VERSION 5.8 ;
BUSBITCHARS "[]" ;
DIVIDERCHAR "/" ;
UNITS
    DATABASE MICRONS 1000 ;
END UNITS

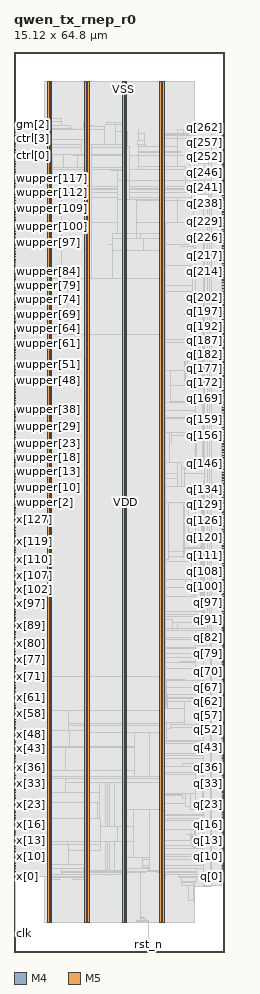
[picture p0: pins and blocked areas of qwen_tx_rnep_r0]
MACRO qwen_tx_rnep_r0
  FOREIGN qwen_tx_rnep_r0 0 0 ;
  CLASS BLOCK ;
  SIZE 15.12 BY 64.8 ;
  PIN clk
    DIRECTION INPUT ;
    USE SIGNAL ;
    PORT
      LAYER M4 ;
        RECT  0.054 1.296 0.138 1.32 ;
    END
    PORT
      LAYER M4 ;
        RECT  0.108 1.296 0.227 1.416 ;
    END
  END clk
  PIN ctrl[0]
    DIRECTION INPUT ;
    USE SIGNAL ;
    PORT
      LAYER M4 ;
        RECT  0.054 57.36 0.138 57.384 ;
    END
  END ctrl[0]
  PIN ctrl[1]
    DIRECTION INPUT ;
    USE SIGNAL ;
    PORT
      LAYER M4 ;
        RECT  0.054 57.552 0.138 57.576 ;
    END
  END ctrl[1]
  PIN ctrl[2]
    DIRECTION INPUT ;
    USE SIGNAL ;
    PORT
      LAYER M4 ;
        RECT  0.054 57.744 0.138 57.768 ;
    END
  END ctrl[2]
  PIN ctrl[3]
    DIRECTION INPUT ;
    USE SIGNAL ;
    PORT
      LAYER M4 ;
        RECT  0.054 57.984 0.138 58.008 ;
    END
  END ctrl[3]
  PIN ctrl[4]
    DIRECTION INPUT ;
    USE SIGNAL ;
    PORT
      LAYER M4 ;
        RECT  0.054 58.176 0.138 58.2 ;
    END
  END ctrl[4]
  PIN ctrl[5]
    DIRECTION INPUT ;
    USE SIGNAL ;
    PORT
      LAYER M4 ;
        RECT  0.054 58.368 0.138 58.392 ;
    END
  END ctrl[5]
  PIN gm[0]
    DIRECTION INPUT ;
    USE SIGNAL ;
    PORT
      LAYER M4 ;
        RECT  0.054 58.56 0.138 58.584 ;
    END
  END gm[0]
  PIN gm[1]
    DIRECTION INPUT ;
    USE SIGNAL ;
    PORT
      LAYER M4 ;
        RECT  0.054 58.8 0.138 58.824 ;
    END
  END gm[1]
  PIN gm[2]
    DIRECTION INPUT ;
    USE SIGNAL ;
    PORT
      LAYER M4 ;
        RECT  0.054 58.992 0.138 59.016 ;
    END
  END gm[2]
  PIN gm[3]
    DIRECTION INPUT ;
    USE SIGNAL ;
    PORT
      LAYER M4 ;
        RECT  0.054 59.184 0.138 59.208 ;
    END
  END gm[3]
  PIN q[0]
    DIRECTION OUTPUT ;
    USE SIGNAL ;
    PORT
      LAYER M4 ;
        RECT  14.982 5.424 15.066 5.448 ;
    END
  END q[0]
  PIN q[100]
    DIRECTION OUTPUT ;
    USE SIGNAL ;
    PORT
      LAYER M4 ;
        RECT  14.982 25.776 15.066 25.8 ;
    END
  END q[100]
  PIN q[101]
    DIRECTION OUTPUT ;
    USE SIGNAL ;
    PORT
      LAYER M4 ;
        RECT  14.982 25.968 15.066 25.992 ;
    END
  END q[101]
  PIN q[102]
    DIRECTION OUTPUT ;
    USE SIGNAL ;
    PORT
      LAYER M4 ;
        RECT  14.982 26.16 15.066 26.184 ;
    END
  END q[102]
  PIN q[103]
    DIRECTION OUTPUT ;
    USE SIGNAL ;
    PORT
      LAYER M4 ;
        RECT  14.982 26.4 15.066 26.424 ;
    END
  END q[103]
  PIN q[104]
    DIRECTION OUTPUT ;
    USE SIGNAL ;
    PORT
      LAYER M4 ;
        RECT  14.982 26.592 15.066 26.616 ;
    END
  END q[104]
  PIN q[105]
    DIRECTION OUTPUT ;
    USE SIGNAL ;
    PORT
      LAYER M4 ;
        RECT  14.982 26.784 15.066 26.808 ;
    END
  END q[105]
  PIN q[106]
    DIRECTION OUTPUT ;
    USE SIGNAL ;
    PORT
      LAYER M4 ;
        RECT  14.982 26.976 15.066 27 ;
    END
  END q[106]
  PIN q[107]
    DIRECTION OUTPUT ;
    USE SIGNAL ;
    PORT
      LAYER M4 ;
        RECT  14.982 27.168 15.066 27.192 ;
    END
  END q[107]
  PIN q[108]
    DIRECTION OUTPUT ;
    USE SIGNAL ;
    PORT
      LAYER M4 ;
        RECT  14.982 27.408 15.066 27.432 ;
    END
  END q[108]
  PIN q[109]
    DIRECTION OUTPUT ;
    USE SIGNAL ;
    PORT
      LAYER M4 ;
        RECT  14.982 27.6 15.066 27.624 ;
    END
  END q[109]
  PIN q[10]
    DIRECTION OUTPUT ;
    USE SIGNAL ;
    PORT
      LAYER M4 ;
        RECT  14.982 7.44 15.066 7.464 ;
    END
  END q[10]
  PIN q[110]
    DIRECTION OUTPUT ;
    USE SIGNAL ;
    PORT
      LAYER M4 ;
        RECT  14.982 27.792 15.066 27.816 ;
    END
  END q[110]
  PIN q[111]
    DIRECTION OUTPUT ;
    USE SIGNAL ;
    PORT
      LAYER M4 ;
        RECT  14.982 27.984 15.066 28.008 ;
    END
  END q[111]
  PIN q[112]
    DIRECTION OUTPUT ;
    USE SIGNAL ;
    PORT
      LAYER M4 ;
        RECT  14.982 28.224 15.066 28.248 ;
    END
  END q[112]
  PIN q[113]
    DIRECTION OUTPUT ;
    USE SIGNAL ;
    PORT
      LAYER M4 ;
        RECT  14.982 28.416 15.066 28.44 ;
    END
  END q[113]
  PIN q[114]
    DIRECTION OUTPUT ;
    USE SIGNAL ;
    PORT
      LAYER M4 ;
        RECT  14.982 28.608 15.066 28.632 ;
    END
  END q[114]
  PIN q[115]
    DIRECTION OUTPUT ;
    USE SIGNAL ;
    PORT
      LAYER M4 ;
        RECT  14.982 28.8 15.066 28.824 ;
    END
  END q[115]
  PIN q[116]
    DIRECTION OUTPUT ;
    USE SIGNAL ;
    PORT
      LAYER M4 ;
        RECT  14.982 29.04 15.066 29.064 ;
    END
  END q[116]
  PIN q[117]
    DIRECTION OUTPUT ;
    USE SIGNAL ;
    PORT
      LAYER M4 ;
        RECT  14.982 29.232 15.066 29.256 ;
    END
  END q[117]
  PIN q[118]
    DIRECTION OUTPUT ;
    USE SIGNAL ;
    PORT
      LAYER M4 ;
        RECT  14.982 29.424 15.066 29.448 ;
    END
  END q[118]
  PIN q[119]
    DIRECTION OUTPUT ;
    USE SIGNAL ;
    PORT
      LAYER M4 ;
        RECT  14.982 29.616 15.066 29.64 ;
    END
  END q[119]
  PIN q[11]
    DIRECTION OUTPUT ;
    USE SIGNAL ;
    PORT
      LAYER M4 ;
        RECT  14.982 7.632 15.066 7.656 ;
    END
  END q[11]
  PIN q[120]
    DIRECTION OUTPUT ;
    USE SIGNAL ;
    PORT
      LAYER M4 ;
        RECT  14.982 29.856 15.066 29.88 ;
    END
  END q[120]
  PIN q[121]
    DIRECTION OUTPUT ;
    USE SIGNAL ;
    PORT
      LAYER M4 ;
        RECT  14.982 30.048 15.066 30.072 ;
    END
  END q[121]
  PIN q[122]
    DIRECTION OUTPUT ;
    USE SIGNAL ;
    PORT
      LAYER M4 ;
        RECT  14.982 30.24 15.066 30.264 ;
    END
  END q[122]
  PIN q[123]
    DIRECTION OUTPUT ;
    USE SIGNAL ;
    PORT
      LAYER M4 ;
        RECT  14.982 30.432 15.066 30.456 ;
    END
  END q[123]
  PIN q[124]
    DIRECTION OUTPUT ;
    USE SIGNAL ;
    PORT
      LAYER M4 ;
        RECT  14.982 30.672 15.066 30.696 ;
    END
  END q[124]
  PIN q[125]
    DIRECTION OUTPUT ;
    USE SIGNAL ;
    PORT
      LAYER M4 ;
        RECT  14.982 30.864 15.066 30.888 ;
    END
  END q[125]
  PIN q[126]
    DIRECTION OUTPUT ;
    USE SIGNAL ;
    PORT
      LAYER M4 ;
        RECT  14.982 31.056 15.066 31.08 ;
    END
  END q[126]
  PIN q[127]
    DIRECTION OUTPUT ;
    USE SIGNAL ;
    PORT
      LAYER M4 ;
        RECT  14.982 31.248 15.066 31.272 ;
    END
  END q[127]
  PIN q[128]
    DIRECTION OUTPUT ;
    USE SIGNAL ;
    PORT
      LAYER M4 ;
        RECT  14.982 31.488 15.066 31.512 ;
    END
  END q[128]
  PIN q[129]
    DIRECTION OUTPUT ;
    USE SIGNAL ;
    PORT
      LAYER M4 ;
        RECT  14.982 31.68 15.066 31.704 ;
    END
  END q[129]
  PIN q[12]
    DIRECTION OUTPUT ;
    USE SIGNAL ;
    PORT
      LAYER M4 ;
        RECT  14.982 7.824 15.066 7.848 ;
    END
  END q[12]
  PIN q[130]
    DIRECTION OUTPUT ;
    USE SIGNAL ;
    PORT
      LAYER M4 ;
        RECT  14.982 31.872 15.066 31.896 ;
    END
  END q[130]
  PIN q[131]
    DIRECTION OUTPUT ;
    USE SIGNAL ;
    PORT
      LAYER M4 ;
        RECT  14.982 32.064 15.066 32.088 ;
    END
  END q[131]
  PIN q[132]
    DIRECTION OUTPUT ;
    USE SIGNAL ;
    PORT
      LAYER M4 ;
        RECT  14.982 32.304 15.066 32.328 ;
    END
  END q[132]
  PIN q[133]
    DIRECTION OUTPUT ;
    USE SIGNAL ;
    PORT
      LAYER M4 ;
        RECT  14.982 32.496 15.066 32.52 ;
    END
  END q[133]
  PIN q[134]
    DIRECTION OUTPUT ;
    USE SIGNAL ;
    PORT
      LAYER M4 ;
        RECT  14.982 32.688 15.066 32.712 ;
    END
  END q[134]
  PIN q[135]
    DIRECTION OUTPUT ;
    USE SIGNAL ;
    PORT
      LAYER M4 ;
        RECT  14.982 32.88 15.066 32.904 ;
    END
  END q[135]
  PIN q[136]
    DIRECTION OUTPUT ;
    USE SIGNAL ;
    PORT
      LAYER M4 ;
        RECT  14.982 33.12 15.066 33.144 ;
    END
  END q[136]
  PIN q[137]
    DIRECTION OUTPUT ;
    USE SIGNAL ;
    PORT
      LAYER M4 ;
        RECT  14.982 33.312 15.066 33.336 ;
    END
  END q[137]
  PIN q[138]
    DIRECTION OUTPUT ;
    USE SIGNAL ;
    PORT
      LAYER M4 ;
        RECT  14.982 33.504 15.066 33.528 ;
    END
  END q[138]
  PIN q[139]
    DIRECTION OUTPUT ;
    USE SIGNAL ;
    PORT
      LAYER M4 ;
        RECT  14.982 33.696 15.066 33.72 ;
    END
  END q[139]
  PIN q[13]
    DIRECTION OUTPUT ;
    USE SIGNAL ;
    PORT
      LAYER M4 ;
        RECT  14.982 8.016 15.066 8.04 ;
    END
  END q[13]
  PIN q[140]
    DIRECTION OUTPUT ;
    USE SIGNAL ;
    PORT
      LAYER M4 ;
        RECT  14.982 33.936 15.066 33.96 ;
    END
  END q[140]
  PIN q[141]
    DIRECTION OUTPUT ;
    USE SIGNAL ;
    PORT
      LAYER M4 ;
        RECT  14.982 34.128 15.066 34.152 ;
    END
  END q[141]
  PIN q[142]
    DIRECTION OUTPUT ;
    USE SIGNAL ;
    PORT
      LAYER M4 ;
        RECT  14.982 34.32 15.066 34.344 ;
    END
  END q[142]
  PIN q[143]
    DIRECTION OUTPUT ;
    USE SIGNAL ;
    PORT
      LAYER M4 ;
        RECT  14.982 34.512 15.066 34.536 ;
    END
  END q[143]
  PIN q[144]
    DIRECTION OUTPUT ;
    USE SIGNAL ;
    PORT
      LAYER M4 ;
        RECT  14.982 34.752 15.066 34.776 ;
    END
  END q[144]
  PIN q[145]
    DIRECTION OUTPUT ;
    USE SIGNAL ;
    PORT
      LAYER M4 ;
        RECT  14.982 34.944 15.066 34.968 ;
    END
  END q[145]
  PIN q[146]
    DIRECTION OUTPUT ;
    USE SIGNAL ;
    PORT
      LAYER M4 ;
        RECT  14.982 35.136 15.066 35.16 ;
    END
  END q[146]
  PIN q[147]
    DIRECTION OUTPUT ;
    USE SIGNAL ;
    PORT
      LAYER M4 ;
        RECT  14.982 35.328 15.066 35.352 ;
    END
  END q[147]
  PIN q[148]
    DIRECTION OUTPUT ;
    USE SIGNAL ;
    PORT
      LAYER M4 ;
        RECT  14.982 35.568 15.066 35.592 ;
    END
  END q[148]
  PIN q[149]
    DIRECTION OUTPUT ;
    USE SIGNAL ;
    PORT
      LAYER M4 ;
        RECT  14.982 35.76 15.066 35.784 ;
    END
  END q[149]
  PIN q[14]
    DIRECTION OUTPUT ;
    USE SIGNAL ;
    PORT
      LAYER M4 ;
        RECT  14.982 8.256 15.066 8.28 ;
    END
  END q[14]
  PIN q[150]
    DIRECTION OUTPUT ;
    USE SIGNAL ;
    PORT
      LAYER M4 ;
        RECT  14.982 35.952 15.066 35.976 ;
    END
  END q[150]
  PIN q[151]
    DIRECTION OUTPUT ;
    USE SIGNAL ;
    PORT
      LAYER M4 ;
        RECT  14.982 36.144 15.066 36.168 ;
    END
  END q[151]
  PIN q[152]
    DIRECTION OUTPUT ;
    USE SIGNAL ;
    PORT
      LAYER M4 ;
        RECT  14.982 36.384 15.066 36.408 ;
    END
  END q[152]
  PIN q[153]
    DIRECTION OUTPUT ;
    USE SIGNAL ;
    PORT
      LAYER M4 ;
        RECT  14.982 36.576 15.066 36.6 ;
    END
  END q[153]
  PIN q[154]
    DIRECTION OUTPUT ;
    USE SIGNAL ;
    PORT
      LAYER M4 ;
        RECT  14.982 36.768 15.066 36.792 ;
    END
  END q[154]
  PIN q[155]
    DIRECTION OUTPUT ;
    USE SIGNAL ;
    PORT
      LAYER M4 ;
        RECT  14.982 36.96 15.066 36.984 ;
    END
  END q[155]
  PIN q[156]
    DIRECTION OUTPUT ;
    USE SIGNAL ;
    PORT
      LAYER M4 ;
        RECT  14.982 37.2 15.066 37.224 ;
    END
  END q[156]
  PIN q[157]
    DIRECTION OUTPUT ;
    USE SIGNAL ;
    PORT
      LAYER M4 ;
        RECT  14.982 37.392 15.066 37.416 ;
    END
  END q[157]
  PIN q[158]
    DIRECTION OUTPUT ;
    USE SIGNAL ;
    PORT
      LAYER M4 ;
        RECT  14.982 37.584 15.066 37.608 ;
    END
  END q[158]
  PIN q[159]
    DIRECTION OUTPUT ;
    USE SIGNAL ;
    PORT
      LAYER M4 ;
        RECT  14.982 37.776 15.066 37.8 ;
    END
  END q[159]
  PIN q[15]
    DIRECTION OUTPUT ;
    USE SIGNAL ;
    PORT
      LAYER M4 ;
        RECT  14.982 8.448 15.066 8.472 ;
    END
  END q[15]
  PIN q[160]
    DIRECTION OUTPUT ;
    USE SIGNAL ;
    PORT
      LAYER M4 ;
        RECT  14.982 37.968 15.066 37.992 ;
    END
  END q[160]
  PIN q[161]
    DIRECTION OUTPUT ;
    USE SIGNAL ;
    PORT
      LAYER M4 ;
        RECT  14.982 38.208 15.066 38.232 ;
    END
  END q[161]
  PIN q[162]
    DIRECTION OUTPUT ;
    USE SIGNAL ;
    PORT
      LAYER M4 ;
        RECT  14.982 38.4 15.066 38.424 ;
    END
  END q[162]
  PIN q[163]
    DIRECTION OUTPUT ;
    USE SIGNAL ;
    PORT
      LAYER M4 ;
        RECT  14.982 38.592 15.066 38.616 ;
    END
  END q[163]
  PIN q[164]
    DIRECTION OUTPUT ;
    USE SIGNAL ;
    PORT
      LAYER M4 ;
        RECT  14.982 38.784 15.066 38.808 ;
    END
  END q[164]
  PIN q[165]
    DIRECTION OUTPUT ;
    USE SIGNAL ;
    PORT
      LAYER M4 ;
        RECT  14.982 39.024 15.066 39.048 ;
    END
  END q[165]
  PIN q[166]
    DIRECTION OUTPUT ;
    USE SIGNAL ;
    PORT
      LAYER M4 ;
        RECT  14.982 39.216 15.066 39.24 ;
    END
  END q[166]
  PIN q[167]
    DIRECTION OUTPUT ;
    USE SIGNAL ;
    PORT
      LAYER M4 ;
        RECT  14.982 39.408 15.066 39.432 ;
    END
  END q[167]
  PIN q[168]
    DIRECTION OUTPUT ;
    USE SIGNAL ;
    PORT
      LAYER M4 ;
        RECT  14.982 39.6 15.066 39.624 ;
    END
  END q[168]
  PIN q[169]
    DIRECTION OUTPUT ;
    USE SIGNAL ;
    PORT
      LAYER M4 ;
        RECT  14.982 39.84 15.066 39.864 ;
    END
  END q[169]
  PIN q[16]
    DIRECTION OUTPUT ;
    USE SIGNAL ;
    PORT
      LAYER M4 ;
        RECT  14.982 8.64 15.066 8.664 ;
    END
  END q[16]
  PIN q[170]
    DIRECTION OUTPUT ;
    USE SIGNAL ;
    PORT
      LAYER M4 ;
        RECT  14.982 40.032 15.066 40.056 ;
    END
  END q[170]
  PIN q[171]
    DIRECTION OUTPUT ;
    USE SIGNAL ;
    PORT
      LAYER M4 ;
        RECT  14.982 40.224 15.066 40.248 ;
    END
  END q[171]
  PIN q[172]
    DIRECTION OUTPUT ;
    USE SIGNAL ;
    PORT
      LAYER M4 ;
        RECT  14.982 40.416 15.066 40.44 ;
    END
  END q[172]
  PIN q[173]
    DIRECTION OUTPUT ;
    USE SIGNAL ;
    PORT
      LAYER M4 ;
        RECT  14.982 40.656 15.066 40.68 ;
    END
  END q[173]
  PIN q[174]
    DIRECTION OUTPUT ;
    USE SIGNAL ;
    PORT
      LAYER M4 ;
        RECT  14.982 40.848 15.066 40.872 ;
    END
  END q[174]
  PIN q[175]
    DIRECTION OUTPUT ;
    USE SIGNAL ;
    PORT
      LAYER M4 ;
        RECT  14.982 41.04 15.066 41.064 ;
    END
  END q[175]
  PIN q[176]
    DIRECTION OUTPUT ;
    USE SIGNAL ;
    PORT
      LAYER M4 ;
        RECT  14.982 41.232 15.066 41.256 ;
    END
  END q[176]
  PIN q[177]
    DIRECTION OUTPUT ;
    USE SIGNAL ;
    PORT
      LAYER M4 ;
        RECT  14.982 41.472 15.066 41.496 ;
    END
  END q[177]
  PIN q[178]
    DIRECTION OUTPUT ;
    USE SIGNAL ;
    PORT
      LAYER M4 ;
        RECT  14.982 41.664 15.066 41.688 ;
    END
  END q[178]
  PIN q[179]
    DIRECTION OUTPUT ;
    USE SIGNAL ;
    PORT
      LAYER M4 ;
        RECT  14.982 41.856 15.066 41.88 ;
    END
  END q[179]
  PIN q[17]
    DIRECTION OUTPUT ;
    USE SIGNAL ;
    PORT
      LAYER M4 ;
        RECT  14.982 8.832 15.066 8.856 ;
    END
  END q[17]
  PIN q[180]
    DIRECTION OUTPUT ;
    USE SIGNAL ;
    PORT
      LAYER M4 ;
        RECT  14.982 42.048 15.066 42.072 ;
    END
  END q[180]
  PIN q[181]
    DIRECTION OUTPUT ;
    USE SIGNAL ;
    PORT
      LAYER M4 ;
        RECT  14.982 42.288 15.066 42.312 ;
    END
  END q[181]
  PIN q[182]
    DIRECTION OUTPUT ;
    USE SIGNAL ;
    PORT
      LAYER M4 ;
        RECT  14.982 42.48 15.066 42.504 ;
    END
  END q[182]
  PIN q[183]
    DIRECTION OUTPUT ;
    USE SIGNAL ;
    PORT
      LAYER M4 ;
        RECT  14.982 42.672 15.066 42.696 ;
    END
  END q[183]
  PIN q[184]
    DIRECTION OUTPUT ;
    USE SIGNAL ;
    PORT
      LAYER M4 ;
        RECT  14.982 42.864 15.066 42.888 ;
    END
  END q[184]
  PIN q[185]
    DIRECTION OUTPUT ;
    USE SIGNAL ;
    PORT
      LAYER M4 ;
        RECT  14.982 43.104 15.066 43.128 ;
    END
  END q[185]
  PIN q[186]
    DIRECTION OUTPUT ;
    USE SIGNAL ;
    PORT
      LAYER M4 ;
        RECT  14.982 43.296 15.066 43.32 ;
    END
  END q[186]
  PIN q[187]
    DIRECTION OUTPUT ;
    USE SIGNAL ;
    PORT
      LAYER M4 ;
        RECT  14.982 43.488 15.066 43.512 ;
    END
  END q[187]
  PIN q[188]
    DIRECTION OUTPUT ;
    USE SIGNAL ;
    PORT
      LAYER M4 ;
        RECT  14.982 43.68 15.066 43.704 ;
    END
  END q[188]
  PIN q[189]
    DIRECTION OUTPUT ;
    USE SIGNAL ;
    PORT
      LAYER M4 ;
        RECT  14.982 43.92 15.066 43.944 ;
    END
  END q[189]
  PIN q[18]
    DIRECTION OUTPUT ;
    USE SIGNAL ;
    PORT
      LAYER M4 ;
        RECT  14.982 9.072 15.066 9.096 ;
    END
  END q[18]
  PIN q[190]
    DIRECTION OUTPUT ;
    USE SIGNAL ;
    PORT
      LAYER M4 ;
        RECT  14.982 44.112 15.066 44.136 ;
    END
  END q[190]
  PIN q[191]
    DIRECTION OUTPUT ;
    USE SIGNAL ;
    PORT
      LAYER M4 ;
        RECT  14.982 44.304 15.066 44.328 ;
    END
  END q[191]
  PIN q[192]
    DIRECTION OUTPUT ;
    USE SIGNAL ;
    PORT
      LAYER M4 ;
        RECT  14.982 44.496 15.066 44.52 ;
    END
  END q[192]
  PIN q[193]
    DIRECTION OUTPUT ;
    USE SIGNAL ;
    PORT
      LAYER M4 ;
        RECT  14.982 44.736 15.066 44.76 ;
    END
  END q[193]
  PIN q[194]
    DIRECTION OUTPUT ;
    USE SIGNAL ;
    PORT
      LAYER M4 ;
        RECT  14.982 44.928 15.066 44.952 ;
    END
  END q[194]
  PIN q[195]
    DIRECTION OUTPUT ;
    USE SIGNAL ;
    PORT
      LAYER M4 ;
        RECT  14.982 45.12 15.066 45.144 ;
    END
  END q[195]
  PIN q[196]
    DIRECTION OUTPUT ;
    USE SIGNAL ;
    PORT
      LAYER M4 ;
        RECT  14.982 45.312 15.066 45.336 ;
    END
  END q[196]
  PIN q[197]
    DIRECTION OUTPUT ;
    USE SIGNAL ;
    PORT
      LAYER M4 ;
        RECT  14.982 45.552 15.066 45.576 ;
    END
  END q[197]
  PIN q[198]
    DIRECTION OUTPUT ;
    USE SIGNAL ;
    PORT
      LAYER M4 ;
        RECT  14.982 45.744 15.066 45.768 ;
    END
  END q[198]
  PIN q[199]
    DIRECTION OUTPUT ;
    USE SIGNAL ;
    PORT
      LAYER M4 ;
        RECT  14.982 45.936 15.066 45.96 ;
    END
  END q[199]
  PIN q[19]
    DIRECTION OUTPUT ;
    USE SIGNAL ;
    PORT
      LAYER M4 ;
        RECT  14.982 9.264 15.066 9.288 ;
    END
  END q[19]
  PIN q[1]
    DIRECTION OUTPUT ;
    USE SIGNAL ;
    PORT
      LAYER M4 ;
        RECT  14.982 5.568 15.066 5.592 ;
    END
  END q[1]
  PIN q[200]
    DIRECTION OUTPUT ;
    USE SIGNAL ;
    PORT
      LAYER M4 ;
        RECT  14.982 46.128 15.066 46.152 ;
    END
  END q[200]
  PIN q[201]
    DIRECTION OUTPUT ;
    USE SIGNAL ;
    PORT
      LAYER M4 ;
        RECT  14.982 46.368 15.066 46.392 ;
    END
  END q[201]
  PIN q[202]
    DIRECTION OUTPUT ;
    USE SIGNAL ;
    PORT
      LAYER M4 ;
        RECT  14.982 46.56 15.066 46.584 ;
    END
  END q[202]
  PIN q[203]
    DIRECTION OUTPUT ;
    USE SIGNAL ;
    PORT
      LAYER M4 ;
        RECT  14.982 46.752 15.066 46.776 ;
    END
  END q[203]
  PIN q[204]
    DIRECTION OUTPUT ;
    USE SIGNAL ;
    PORT
      LAYER M4 ;
        RECT  14.982 46.944 15.066 46.968 ;
    END
  END q[204]
  PIN q[205]
    DIRECTION OUTPUT ;
    USE SIGNAL ;
    PORT
      LAYER M4 ;
        RECT  14.982 47.184 15.066 47.208 ;
    END
  END q[205]
  PIN q[206]
    DIRECTION OUTPUT ;
    USE SIGNAL ;
    PORT
      LAYER M4 ;
        RECT  14.982 47.376 15.066 47.4 ;
    END
  END q[206]
  PIN q[207]
    DIRECTION OUTPUT ;
    USE SIGNAL ;
    PORT
      LAYER M4 ;
        RECT  14.982 47.568 15.066 47.592 ;
    END
  END q[207]
  PIN q[208]
    DIRECTION OUTPUT ;
    USE SIGNAL ;
    PORT
      LAYER M4 ;
        RECT  14.982 47.76 15.066 47.784 ;
    END
  END q[208]
  PIN q[209]
    DIRECTION OUTPUT ;
    USE SIGNAL ;
    PORT
      LAYER M4 ;
        RECT  14.982 48 15.066 48.024 ;
    END
  END q[209]
  PIN q[20]
    DIRECTION OUTPUT ;
    USE SIGNAL ;
    PORT
      LAYER M4 ;
        RECT  14.982 9.456 15.066 9.48 ;
    END
  END q[20]
  PIN q[210]
    DIRECTION OUTPUT ;
    USE SIGNAL ;
    PORT
      LAYER M4 ;
        RECT  14.982 48.192 15.066 48.216 ;
    END
  END q[210]
  PIN q[211]
    DIRECTION OUTPUT ;
    USE SIGNAL ;
    PORT
      LAYER M4 ;
        RECT  14.982 48.384 15.066 48.408 ;
    END
  END q[211]
  PIN q[212]
    DIRECTION OUTPUT ;
    USE SIGNAL ;
    PORT
      LAYER M4 ;
        RECT  14.982 48.576 15.066 48.6 ;
    END
  END q[212]
  PIN q[213]
    DIRECTION OUTPUT ;
    USE SIGNAL ;
    PORT
      LAYER M4 ;
        RECT  14.982 48.768 15.066 48.792 ;
    END
  END q[213]
  PIN q[214]
    DIRECTION OUTPUT ;
    USE SIGNAL ;
    PORT
      LAYER M4 ;
        RECT  14.982 49.008 15.066 49.032 ;
    END
  END q[214]
  PIN q[215]
    DIRECTION OUTPUT ;
    USE SIGNAL ;
    PORT
      LAYER M4 ;
        RECT  14.982 49.2 15.066 49.224 ;
    END
  END q[215]
  PIN q[216]
    DIRECTION OUTPUT ;
    USE SIGNAL ;
    PORT
      LAYER M4 ;
        RECT  14.982 49.392 15.066 49.416 ;
    END
  END q[216]
  PIN q[217]
    DIRECTION OUTPUT ;
    USE SIGNAL ;
    PORT
      LAYER M4 ;
        RECT  14.982 49.584 15.066 49.608 ;
    END
  END q[217]
  PIN q[218]
    DIRECTION OUTPUT ;
    USE SIGNAL ;
    PORT
      LAYER M4 ;
        RECT  14.982 49.824 15.066 49.848 ;
    END
  END q[218]
  PIN q[219]
    DIRECTION OUTPUT ;
    USE SIGNAL ;
    PORT
      LAYER M4 ;
        RECT  14.982 50.016 15.066 50.04 ;
    END
  END q[219]
  PIN q[21]
    DIRECTION OUTPUT ;
    USE SIGNAL ;
    PORT
      LAYER M4 ;
        RECT  14.982 9.648 15.066 9.672 ;
    END
  END q[21]
  PIN q[220]
    DIRECTION OUTPUT ;
    USE SIGNAL ;
    PORT
      LAYER M4 ;
        RECT  14.982 50.208 15.066 50.232 ;
    END
  END q[220]
  PIN q[221]
    DIRECTION OUTPUT ;
    USE SIGNAL ;
    PORT
      LAYER M4 ;
        RECT  14.982 50.4 15.066 50.424 ;
    END
  END q[221]
  PIN q[222]
    DIRECTION OUTPUT ;
    USE SIGNAL ;
    PORT
      LAYER M4 ;
        RECT  14.982 50.64 15.066 50.664 ;
    END
  END q[222]
  PIN q[223]
    DIRECTION OUTPUT ;
    USE SIGNAL ;
    PORT
      LAYER M4 ;
        RECT  14.982 50.832 15.066 50.856 ;
    END
  END q[223]
  PIN q[224]
    DIRECTION OUTPUT ;
    USE SIGNAL ;
    PORT
      LAYER M4 ;
        RECT  14.982 51.024 15.066 51.048 ;
    END
  END q[224]
  PIN q[225]
    DIRECTION OUTPUT ;
    USE SIGNAL ;
    PORT
      LAYER M4 ;
        RECT  14.982 51.216 15.066 51.24 ;
    END
  END q[225]
  PIN q[226]
    DIRECTION OUTPUT ;
    USE SIGNAL ;
    PORT
      LAYER M4 ;
        RECT  14.982 51.456 15.066 51.48 ;
    END
  END q[226]
  PIN q[227]
    DIRECTION OUTPUT ;
    USE SIGNAL ;
    PORT
      LAYER M4 ;
        RECT  14.982 51.648 15.066 51.672 ;
    END
  END q[227]
  PIN q[228]
    DIRECTION OUTPUT ;
    USE SIGNAL ;
    PORT
      LAYER M4 ;
        RECT  14.982 51.84 15.066 51.864 ;
    END
  END q[228]
  PIN q[229]
    DIRECTION OUTPUT ;
    USE SIGNAL ;
    PORT
      LAYER M4 ;
        RECT  14.982 52.032 15.066 52.056 ;
    END
  END q[229]
  PIN q[22]
    DIRECTION OUTPUT ;
    USE SIGNAL ;
    PORT
      LAYER M4 ;
        RECT  14.982 9.888 15.066 9.912 ;
    END
  END q[22]
  PIN q[230]
    DIRECTION OUTPUT ;
    USE SIGNAL ;
    PORT
      LAYER M4 ;
        RECT  14.982 52.272 15.066 52.296 ;
    END
  END q[230]
  PIN q[231]
    DIRECTION OUTPUT ;
    USE SIGNAL ;
    PORT
      LAYER M4 ;
        RECT  14.982 52.464 15.066 52.488 ;
    END
  END q[231]
  PIN q[232]
    DIRECTION OUTPUT ;
    USE SIGNAL ;
    PORT
      LAYER M4 ;
        RECT  14.982 52.656 15.066 52.68 ;
    END
  END q[232]
  PIN q[233]
    DIRECTION OUTPUT ;
    USE SIGNAL ;
    PORT
      LAYER M4 ;
        RECT  14.982 52.848 15.066 52.872 ;
    END
  END q[233]
  PIN q[234]
    DIRECTION OUTPUT ;
    USE SIGNAL ;
    PORT
      LAYER M4 ;
        RECT  14.982 53.088 15.066 53.112 ;
    END
  END q[234]
  PIN q[235]
    DIRECTION OUTPUT ;
    USE SIGNAL ;
    PORT
      LAYER M4 ;
        RECT  14.982 53.28 15.066 53.304 ;
    END
  END q[235]
  PIN q[236]
    DIRECTION OUTPUT ;
    USE SIGNAL ;
    PORT
      LAYER M4 ;
        RECT  14.982 53.472 15.066 53.496 ;
    END
  END q[236]
  PIN q[237]
    DIRECTION OUTPUT ;
    USE SIGNAL ;
    PORT
      LAYER M4 ;
        RECT  14.982 53.664 15.066 53.688 ;
    END
  END q[237]
  PIN q[238]
    DIRECTION OUTPUT ;
    USE SIGNAL ;
    PORT
      LAYER M4 ;
        RECT  14.982 53.904 15.066 53.928 ;
    END
  END q[238]
  PIN q[239]
    DIRECTION OUTPUT ;
    USE SIGNAL ;
    PORT
      LAYER M4 ;
        RECT  14.982 54.096 15.066 54.12 ;
    END
  END q[239]
  PIN q[23]
    DIRECTION OUTPUT ;
    USE SIGNAL ;
    PORT
      LAYER M4 ;
        RECT  14.982 10.08 15.066 10.104 ;
    END
  END q[23]
  PIN q[240]
    DIRECTION OUTPUT ;
    USE SIGNAL ;
    PORT
      LAYER M4 ;
        RECT  14.982 54.288 15.066 54.312 ;
    END
    PORT
      LAYER M4 ;
        RECT  15.036 54.192 15.113 54.312 ;
    END
  END q[240]
  PIN q[241]
    DIRECTION OUTPUT ;
    USE SIGNAL ;
    PORT
      LAYER M4 ;
        RECT  14.982 54.48 15.066 54.504 ;
    END
  END q[241]
  PIN q[242]
    DIRECTION OUTPUT ;
    USE SIGNAL ;
    PORT
      LAYER M4 ;
        RECT  14.982 54.72 15.066 54.744 ;
    END
  END q[242]
  PIN q[243]
    DIRECTION OUTPUT ;
    USE SIGNAL ;
    PORT
      LAYER M4 ;
        RECT  14.982 54.912 15.066 54.936 ;
    END
  END q[243]
  PIN q[244]
    DIRECTION OUTPUT ;
    USE SIGNAL ;
    PORT
      LAYER M4 ;
        RECT  14.982 55.104 15.066 55.128 ;
    END
  END q[244]
  PIN q[245]
    DIRECTION OUTPUT ;
    USE SIGNAL ;
    PORT
      LAYER M4 ;
        RECT  14.982 55.296 15.066 55.32 ;
    END
  END q[245]
  PIN q[246]
    DIRECTION OUTPUT ;
    USE SIGNAL ;
    PORT
      LAYER M4 ;
        RECT  14.982 55.536 15.066 55.56 ;
    END
  END q[246]
  PIN q[247]
    DIRECTION OUTPUT ;
    USE SIGNAL ;
    PORT
      LAYER M4 ;
        RECT  14.982 55.728 15.066 55.752 ;
    END
  END q[247]
  PIN q[248]
    DIRECTION OUTPUT ;
    USE SIGNAL ;
    PORT
      LAYER M4 ;
        RECT  14.982 55.92 15.066 55.944 ;
    END
  END q[248]
  PIN q[249]
    DIRECTION OUTPUT ;
    USE SIGNAL ;
    PORT
      LAYER M4 ;
        RECT  14.982 56.112 15.066 56.136 ;
    END
  END q[249]
  PIN q[24]
    DIRECTION OUTPUT ;
    USE SIGNAL ;
    PORT
      LAYER M4 ;
        RECT  14.982 10.272 15.066 10.296 ;
    END
  END q[24]
  PIN q[250]
    DIRECTION OUTPUT ;
    USE SIGNAL ;
    PORT
      LAYER M4 ;
        RECT  14.982 56.352 15.066 56.376 ;
    END
  END q[250]
  PIN q[251]
    DIRECTION OUTPUT ;
    USE SIGNAL ;
    PORT
      LAYER M4 ;
        RECT  14.982 56.544 15.066 56.568 ;
    END
  END q[251]
  PIN q[252]
    DIRECTION OUTPUT ;
    USE SIGNAL ;
    PORT
      LAYER M4 ;
        RECT  14.982 56.736 15.066 56.76 ;
    END
  END q[252]
  PIN q[253]
    DIRECTION OUTPUT ;
    USE SIGNAL ;
    PORT
      LAYER M4 ;
        RECT  14.982 56.928 15.066 56.952 ;
    END
  END q[253]
  PIN q[254]
    DIRECTION OUTPUT ;
    USE SIGNAL ;
    PORT
      LAYER M4 ;
        RECT  14.982 57.168 15.066 57.192 ;
    END
    PORT
      LAYER M4 ;
        RECT  15.036 57.072 15.113 57.192 ;
    END
  END q[254]
  PIN q[255]
    DIRECTION OUTPUT ;
    USE SIGNAL ;
    PORT
      LAYER M4 ;
        RECT  14.982 57.36 15.066 57.384 ;
    END
  END q[255]
  PIN q[256]
    DIRECTION OUTPUT ;
    USE SIGNAL ;
    PORT
      LAYER M4 ;
        RECT  14.982 57.552 15.066 57.576 ;
    END
  END q[256]
  PIN q[257]
    DIRECTION OUTPUT ;
    USE SIGNAL ;
    PORT
      LAYER M4 ;
        RECT  14.982 57.744 15.066 57.768 ;
    END
  END q[257]
  PIN q[258]
    DIRECTION OUTPUT ;
    USE SIGNAL ;
    PORT
      LAYER M4 ;
        RECT  14.982 57.984 15.066 58.008 ;
    END
  END q[258]
  PIN q[259]
    DIRECTION OUTPUT ;
    USE SIGNAL ;
    PORT
      LAYER M4 ;
        RECT  14.982 58.176 15.066 58.2 ;
    END
  END q[259]
  PIN q[25]
    DIRECTION OUTPUT ;
    USE SIGNAL ;
    PORT
      LAYER M4 ;
        RECT  14.982 10.464 15.066 10.488 ;
    END
  END q[25]
  PIN q[260]
    DIRECTION OUTPUT ;
    USE SIGNAL ;
    PORT
      LAYER M4 ;
        RECT  14.982 58.368 15.066 58.392 ;
    END
  END q[260]
  PIN q[261]
    DIRECTION OUTPUT ;
    USE SIGNAL ;
    PORT
      LAYER M4 ;
        RECT  14.982 58.56 15.066 58.584 ;
    END
  END q[261]
  PIN q[262]
    DIRECTION OUTPUT ;
    USE SIGNAL ;
    PORT
      LAYER M4 ;
        RECT  14.982 58.8 15.066 58.824 ;
    END
  END q[262]
  PIN q[263]
    DIRECTION OUTPUT ;
    USE SIGNAL ;
    PORT
      LAYER M4 ;
        RECT  14.982 58.992 15.066 59.016 ;
    END
  END q[263]
  PIN q[264]
    DIRECTION OUTPUT ;
    USE SIGNAL ;
    PORT
      LAYER M4 ;
        RECT  14.982 59.184 15.066 59.208 ;
    END
  END q[264]
  PIN q[265]
    DIRECTION OUTPUT ;
    USE SIGNAL ;
    PORT
      LAYER M4 ;
        RECT  14.982 59.376 15.066 59.4 ;
    END
  END q[265]
  PIN q[26]
    DIRECTION OUTPUT ;
    USE SIGNAL ;
    PORT
      LAYER M4 ;
        RECT  14.982 10.704 15.066 10.728 ;
    END
  END q[26]
  PIN q[27]
    DIRECTION OUTPUT ;
    USE SIGNAL ;
    PORT
      LAYER M4 ;
        RECT  14.982 10.896 15.066 10.92 ;
    END
  END q[27]
  PIN q[28]
    DIRECTION OUTPUT ;
    USE SIGNAL ;
    PORT
      LAYER M4 ;
        RECT  14.982 11.088 15.066 11.112 ;
    END
  END q[28]
  PIN q[29]
    DIRECTION OUTPUT ;
    USE SIGNAL ;
    PORT
      LAYER M4 ;
        RECT  14.982 11.28 15.066 11.304 ;
    END
  END q[29]
  PIN q[2]
    DIRECTION OUTPUT ;
    USE SIGNAL ;
    PORT
      LAYER M4 ;
        RECT  14.982 5.808 15.066 5.832 ;
    END
  END q[2]
  PIN q[30]
    DIRECTION OUTPUT ;
    USE SIGNAL ;
    PORT
      LAYER M4 ;
        RECT  14.982 11.52 15.066 11.544 ;
    END
  END q[30]
  PIN q[31]
    DIRECTION OUTPUT ;
    USE SIGNAL ;
    PORT
      LAYER M4 ;
        RECT  14.982 11.712 15.066 11.736 ;
    END
  END q[31]
  PIN q[32]
    DIRECTION OUTPUT ;
    USE SIGNAL ;
    PORT
      LAYER M4 ;
        RECT  14.982 11.904 15.066 11.928 ;
    END
  END q[32]
  PIN q[33]
    DIRECTION OUTPUT ;
    USE SIGNAL ;
    PORT
      LAYER M4 ;
        RECT  14.982 12.096 15.066 12.12 ;
    END
  END q[33]
  PIN q[34]
    DIRECTION OUTPUT ;
    USE SIGNAL ;
    PORT
      LAYER M4 ;
        RECT  14.982 12.336 15.066 12.36 ;
    END
  END q[34]
  PIN q[35]
    DIRECTION OUTPUT ;
    USE SIGNAL ;
    PORT
      LAYER M4 ;
        RECT  14.982 12.528 15.066 12.552 ;
    END
  END q[35]
  PIN q[36]
    DIRECTION OUTPUT ;
    USE SIGNAL ;
    PORT
      LAYER M4 ;
        RECT  14.982 12.72 15.066 12.744 ;
    END
  END q[36]
  PIN q[37]
    DIRECTION OUTPUT ;
    USE SIGNAL ;
    PORT
      LAYER M4 ;
        RECT  14.982 12.912 15.066 12.936 ;
    END
  END q[37]
  PIN q[38]
    DIRECTION OUTPUT ;
    USE SIGNAL ;
    PORT
      LAYER M4 ;
        RECT  14.982 13.152 15.066 13.176 ;
    END
  END q[38]
  PIN q[39]
    DIRECTION OUTPUT ;
    USE SIGNAL ;
    PORT
      LAYER M4 ;
        RECT  14.982 13.344 15.066 13.368 ;
    END
  END q[39]
  PIN q[3]
    DIRECTION OUTPUT ;
    USE SIGNAL ;
    PORT
      LAYER M4 ;
        RECT  14.982 6 15.066 6.024 ;
    END
  END q[3]
  PIN q[40]
    DIRECTION OUTPUT ;
    USE SIGNAL ;
    PORT
      LAYER M4 ;
        RECT  14.982 13.536 15.066 13.56 ;
    END
  END q[40]
  PIN q[41]
    DIRECTION OUTPUT ;
    USE SIGNAL ;
    PORT
      LAYER M4 ;
        RECT  14.982 13.728 15.066 13.752 ;
    END
  END q[41]
  PIN q[42]
    DIRECTION OUTPUT ;
    USE SIGNAL ;
    PORT
      LAYER M4 ;
        RECT  14.982 13.968 15.066 13.992 ;
    END
  END q[42]
  PIN q[43]
    DIRECTION OUTPUT ;
    USE SIGNAL ;
    PORT
      LAYER M4 ;
        RECT  14.982 14.16 15.066 14.184 ;
    END
  END q[43]
  PIN q[44]
    DIRECTION OUTPUT ;
    USE SIGNAL ;
    PORT
      LAYER M4 ;
        RECT  14.982 14.352 15.066 14.376 ;
    END
  END q[44]
  PIN q[45]
    DIRECTION OUTPUT ;
    USE SIGNAL ;
    PORT
      LAYER M4 ;
        RECT  14.982 14.544 15.066 14.568 ;
    END
  END q[45]
  PIN q[46]
    DIRECTION OUTPUT ;
    USE SIGNAL ;
    PORT
      LAYER M4 ;
        RECT  14.982 14.784 15.066 14.808 ;
    END
  END q[46]
  PIN q[47]
    DIRECTION OUTPUT ;
    USE SIGNAL ;
    PORT
      LAYER M4 ;
        RECT  14.982 14.976 15.066 15 ;
    END
  END q[47]
  PIN q[48]
    DIRECTION OUTPUT ;
    USE SIGNAL ;
    PORT
      LAYER M4 ;
        RECT  14.982 15.168 15.066 15.192 ;
    END
  END q[48]
  PIN q[49]
    DIRECTION OUTPUT ;
    USE SIGNAL ;
    PORT
      LAYER M4 ;
        RECT  14.982 15.36 15.066 15.384 ;
    END
  END q[49]
  PIN q[4]
    DIRECTION OUTPUT ;
    USE SIGNAL ;
    PORT
      LAYER M4 ;
        RECT  14.982 6.192 15.066 6.216 ;
    END
  END q[4]
  PIN q[50]
    DIRECTION OUTPUT ;
    USE SIGNAL ;
    PORT
      LAYER M4 ;
        RECT  14.982 15.6 15.066 15.624 ;
    END
  END q[50]
  PIN q[51]
    DIRECTION OUTPUT ;
    USE SIGNAL ;
    PORT
      LAYER M4 ;
        RECT  14.982 15.792 15.066 15.816 ;
    END
  END q[51]
  PIN q[52]
    DIRECTION OUTPUT ;
    USE SIGNAL ;
    PORT
      LAYER M4 ;
        RECT  14.982 15.984 15.066 16.008 ;
    END
  END q[52]
  PIN q[53]
    DIRECTION OUTPUT ;
    USE SIGNAL ;
    PORT
      LAYER M4 ;
        RECT  14.982 16.176 15.066 16.2 ;
    END
  END q[53]
  PIN q[54]
    DIRECTION OUTPUT ;
    USE SIGNAL ;
    PORT
      LAYER M4 ;
        RECT  14.982 16.368 15.066 16.392 ;
    END
  END q[54]
  PIN q[55]
    DIRECTION OUTPUT ;
    USE SIGNAL ;
    PORT
      LAYER M4 ;
        RECT  14.982 16.608 15.066 16.632 ;
    END
  END q[55]
  PIN q[56]
    DIRECTION OUTPUT ;
    USE SIGNAL ;
    PORT
      LAYER M4 ;
        RECT  14.982 16.8 15.066 16.824 ;
    END
  END q[56]
  PIN q[57]
    DIRECTION OUTPUT ;
    USE SIGNAL ;
    PORT
      LAYER M4 ;
        RECT  14.982 16.992 15.066 17.016 ;
    END
  END q[57]
  PIN q[58]
    DIRECTION OUTPUT ;
    USE SIGNAL ;
    PORT
      LAYER M4 ;
        RECT  14.982 17.184 15.066 17.208 ;
    END
  END q[58]
  PIN q[59]
    DIRECTION OUTPUT ;
    USE SIGNAL ;
    PORT
      LAYER M4 ;
        RECT  14.982 17.424 15.066 17.448 ;
    END
  END q[59]
  PIN q[5]
    DIRECTION OUTPUT ;
    USE SIGNAL ;
    PORT
      LAYER M4 ;
        RECT  14.982 6.384 15.066 6.408 ;
    END
  END q[5]
  PIN q[60]
    DIRECTION OUTPUT ;
    USE SIGNAL ;
    PORT
      LAYER M4 ;
        RECT  14.982 17.616 15.066 17.64 ;
    END
  END q[60]
  PIN q[61]
    DIRECTION OUTPUT ;
    USE SIGNAL ;
    PORT
      LAYER M4 ;
        RECT  14.982 17.808 15.066 17.832 ;
    END
  END q[61]
  PIN q[62]
    DIRECTION OUTPUT ;
    USE SIGNAL ;
    PORT
      LAYER M4 ;
        RECT  14.982 18 15.066 18.024 ;
    END
  END q[62]
  PIN q[63]
    DIRECTION OUTPUT ;
    USE SIGNAL ;
    PORT
      LAYER M4 ;
        RECT  14.982 18.24 15.066 18.264 ;
    END
  END q[63]
  PIN q[64]
    DIRECTION OUTPUT ;
    USE SIGNAL ;
    PORT
      LAYER M4 ;
        RECT  14.982 18.432 15.066 18.456 ;
    END
  END q[64]
  PIN q[65]
    DIRECTION OUTPUT ;
    USE SIGNAL ;
    PORT
      LAYER M4 ;
        RECT  14.982 18.624 15.066 18.648 ;
    END
  END q[65]
  PIN q[66]
    DIRECTION OUTPUT ;
    USE SIGNAL ;
    PORT
      LAYER M4 ;
        RECT  14.982 18.816 15.066 18.84 ;
    END
  END q[66]
  PIN q[67]
    DIRECTION OUTPUT ;
    USE SIGNAL ;
    PORT
      LAYER M4 ;
        RECT  14.982 19.056 15.066 19.08 ;
    END
  END q[67]
  PIN q[68]
    DIRECTION OUTPUT ;
    USE SIGNAL ;
    PORT
      LAYER M4 ;
        RECT  14.982 19.248 15.066 19.272 ;
    END
  END q[68]
  PIN q[69]
    DIRECTION OUTPUT ;
    USE SIGNAL ;
    PORT
      LAYER M4 ;
        RECT  14.982 19.44 15.066 19.464 ;
    END
  END q[69]
  PIN q[6]
    DIRECTION OUTPUT ;
    USE SIGNAL ;
    PORT
      LAYER M4 ;
        RECT  14.982 6.624 15.066 6.648 ;
    END
  END q[6]
  PIN q[70]
    DIRECTION OUTPUT ;
    USE SIGNAL ;
    PORT
      LAYER M4 ;
        RECT  14.982 19.632 15.066 19.656 ;
    END
  END q[70]
  PIN q[71]
    DIRECTION OUTPUT ;
    USE SIGNAL ;
    PORT
      LAYER M4 ;
        RECT  14.982 19.872 15.066 19.896 ;
    END
  END q[71]
  PIN q[72]
    DIRECTION OUTPUT ;
    USE SIGNAL ;
    PORT
      LAYER M4 ;
        RECT  14.982 20.064 15.066 20.088 ;
    END
  END q[72]
  PIN q[73]
    DIRECTION OUTPUT ;
    USE SIGNAL ;
    PORT
      LAYER M4 ;
        RECT  14.982 20.256 15.066 20.28 ;
    END
  END q[73]
  PIN q[74]
    DIRECTION OUTPUT ;
    USE SIGNAL ;
    PORT
      LAYER M4 ;
        RECT  14.982 20.448 15.066 20.472 ;
    END
  END q[74]
  PIN q[75]
    DIRECTION OUTPUT ;
    USE SIGNAL ;
    PORT
      LAYER M4 ;
        RECT  14.982 20.688 15.066 20.712 ;
    END
  END q[75]
  PIN q[76]
    DIRECTION OUTPUT ;
    USE SIGNAL ;
    PORT
      LAYER M4 ;
        RECT  14.982 20.88 15.066 20.904 ;
    END
  END q[76]
  PIN q[77]
    DIRECTION OUTPUT ;
    USE SIGNAL ;
    PORT
      LAYER M4 ;
        RECT  14.982 21.072 15.066 21.096 ;
    END
  END q[77]
  PIN q[78]
    DIRECTION OUTPUT ;
    USE SIGNAL ;
    PORT
      LAYER M4 ;
        RECT  14.982 21.264 15.066 21.288 ;
    END
  END q[78]
  PIN q[79]
    DIRECTION OUTPUT ;
    USE SIGNAL ;
    PORT
      LAYER M4 ;
        RECT  14.982 21.504 15.066 21.528 ;
    END
  END q[79]
  PIN q[7]
    DIRECTION OUTPUT ;
    USE SIGNAL ;
    PORT
      LAYER M4 ;
        RECT  14.982 6.816 15.066 6.84 ;
    END
  END q[7]
  PIN q[80]
    DIRECTION OUTPUT ;
    USE SIGNAL ;
    PORT
      LAYER M4 ;
        RECT  14.982 21.696 15.066 21.72 ;
    END
  END q[80]
  PIN q[81]
    DIRECTION OUTPUT ;
    USE SIGNAL ;
    PORT
      LAYER M4 ;
        RECT  14.982 21.888 15.066 21.912 ;
    END
  END q[81]
  PIN q[82]
    DIRECTION OUTPUT ;
    USE SIGNAL ;
    PORT
      LAYER M4 ;
        RECT  14.982 22.08 15.066 22.104 ;
    END
  END q[82]
  PIN q[83]
    DIRECTION OUTPUT ;
    USE SIGNAL ;
    PORT
      LAYER M4 ;
        RECT  14.982 22.32 15.066 22.344 ;
    END
  END q[83]
  PIN q[84]
    DIRECTION OUTPUT ;
    USE SIGNAL ;
    PORT
      LAYER M4 ;
        RECT  14.982 22.512 15.066 22.536 ;
    END
  END q[84]
  PIN q[85]
    DIRECTION OUTPUT ;
    USE SIGNAL ;
    PORT
      LAYER M4 ;
        RECT  14.982 22.704 15.066 22.728 ;
    END
  END q[85]
  PIN q[86]
    DIRECTION OUTPUT ;
    USE SIGNAL ;
    PORT
      LAYER M4 ;
        RECT  14.982 22.896 15.066 22.92 ;
    END
  END q[86]
  PIN q[87]
    DIRECTION OUTPUT ;
    USE SIGNAL ;
    PORT
      LAYER M4 ;
        RECT  14.982 23.136 15.066 23.16 ;
    END
  END q[87]
  PIN q[88]
    DIRECTION OUTPUT ;
    USE SIGNAL ;
    PORT
      LAYER M4 ;
        RECT  14.982 23.328 15.066 23.352 ;
    END
  END q[88]
  PIN q[89]
    DIRECTION OUTPUT ;
    USE SIGNAL ;
    PORT
      LAYER M4 ;
        RECT  14.982 23.52 15.066 23.544 ;
    END
  END q[89]
  PIN q[8]
    DIRECTION OUTPUT ;
    USE SIGNAL ;
    PORT
      LAYER M4 ;
        RECT  14.982 7.008 15.066 7.032 ;
    END
  END q[8]
  PIN q[90]
    DIRECTION OUTPUT ;
    USE SIGNAL ;
    PORT
      LAYER M4 ;
        RECT  14.982 23.712 15.066 23.736 ;
    END
  END q[90]
  PIN q[91]
    DIRECTION OUTPUT ;
    USE SIGNAL ;
    PORT
      LAYER M4 ;
        RECT  14.982 23.952 15.066 23.976 ;
    END
  END q[91]
  PIN q[92]
    DIRECTION OUTPUT ;
    USE SIGNAL ;
    PORT
      LAYER M4 ;
        RECT  14.982 24.144 15.066 24.168 ;
    END
  END q[92]
  PIN q[93]
    DIRECTION OUTPUT ;
    USE SIGNAL ;
    PORT
      LAYER M4 ;
        RECT  14.982 24.336 15.066 24.36 ;
    END
  END q[93]
  PIN q[94]
    DIRECTION OUTPUT ;
    USE SIGNAL ;
    PORT
      LAYER M4 ;
        RECT  14.982 24.528 15.066 24.552 ;
    END
  END q[94]
  PIN q[95]
    DIRECTION OUTPUT ;
    USE SIGNAL ;
    PORT
      LAYER M4 ;
        RECT  14.982 24.768 15.066 24.792 ;
    END
  END q[95]
  PIN q[96]
    DIRECTION OUTPUT ;
    USE SIGNAL ;
    PORT
      LAYER M4 ;
        RECT  14.982 24.96 15.066 24.984 ;
    END
  END q[96]
  PIN q[97]
    DIRECTION OUTPUT ;
    USE SIGNAL ;
    PORT
      LAYER M4 ;
        RECT  14.982 25.152 15.066 25.176 ;
    END
  END q[97]
  PIN q[98]
    DIRECTION OUTPUT ;
    USE SIGNAL ;
    PORT
      LAYER M4 ;
        RECT  14.982 25.344 15.066 25.368 ;
    END
  END q[98]
  PIN q[99]
    DIRECTION OUTPUT ;
    USE SIGNAL ;
    PORT
      LAYER M4 ;
        RECT  14.982 25.584 15.066 25.608 ;
    END
  END q[99]
  PIN q[9]
    DIRECTION OUTPUT ;
    USE SIGNAL ;
    PORT
      LAYER M4 ;
        RECT  14.982 7.2 15.066 7.224 ;
    END
  END q[9]
  PIN round
    DIRECTION INPUT ;
    USE SIGNAL ;
    PORT
      LAYER M4 ;
        RECT  0.054 59.376 0.138 59.4 ;
    END
  END round
  PIN rst_n
    DIRECTION INPUT ;
    USE SIGNAL ;
    PORT
      LAYER M5 ;
        RECT  9.696 0.054 9.72 0.138 ;
    END
    PORT
      LAYER M5 ;
        RECT  9.696 0.08 9.72 0.611 ;
    END
  END rst_n
  PIN wupper[0]
    DIRECTION INPUT ;
    USE SIGNAL ;
    PORT
      LAYER M4 ;
        RECT  0.054 31.392 0.138 31.416 ;
    END
  END wupper[0]
  PIN wupper[100]
    DIRECTION INPUT ;
    USE SIGNAL ;
    PORT
      LAYER M4 ;
        RECT  0.054 51.696 0.138 51.72 ;
    END
  END wupper[100]
  PIN wupper[101]
    DIRECTION INPUT ;
    USE SIGNAL ;
    PORT
      LAYER M4 ;
        RECT  0.054 51.888 0.138 51.912 ;
    END
  END wupper[101]
  PIN wupper[102]
    DIRECTION INPUT ;
    USE SIGNAL ;
    PORT
      LAYER M4 ;
        RECT  0.054 52.08 0.138 52.104 ;
    END
  END wupper[102]
  PIN wupper[103]
    DIRECTION INPUT ;
    USE SIGNAL ;
    PORT
      LAYER M4 ;
        RECT  0.054 52.272 0.138 52.296 ;
    END
  END wupper[103]
  PIN wupper[104]
    DIRECTION INPUT ;
    USE SIGNAL ;
    PORT
      LAYER M4 ;
        RECT  0.054 52.464 0.138 52.488 ;
    END
  END wupper[104]
  PIN wupper[105]
    DIRECTION INPUT ;
    USE SIGNAL ;
    PORT
      LAYER M4 ;
        RECT  0.054 52.704 0.138 52.728 ;
    END
  END wupper[105]
  PIN wupper[106]
    DIRECTION INPUT ;
    USE SIGNAL ;
    PORT
      LAYER M4 ;
        RECT  0.054 52.896 0.138 52.92 ;
    END
  END wupper[106]
  PIN wupper[107]
    DIRECTION INPUT ;
    USE SIGNAL ;
    PORT
      LAYER M4 ;
        RECT  0.054 53.088 0.138 53.112 ;
    END
  END wupper[107]
  PIN wupper[108]
    DIRECTION INPUT ;
    USE SIGNAL ;
    PORT
      LAYER M4 ;
        RECT  0.054 53.28 0.138 53.304 ;
    END
  END wupper[108]
  PIN wupper[109]
    DIRECTION INPUT ;
    USE SIGNAL ;
    PORT
      LAYER M4 ;
        RECT  0.054 53.52 0.138 53.544 ;
    END
  END wupper[109]
  PIN wupper[10]
    DIRECTION INPUT ;
    USE SIGNAL ;
    PORT
      LAYER M4 ;
        RECT  0.054 33.408 0.138 33.432 ;
    END
  END wupper[10]
  PIN wupper[110]
    DIRECTION INPUT ;
    USE SIGNAL ;
    PORT
      LAYER M4 ;
        RECT  0.054 53.712 0.138 53.736 ;
    END
  END wupper[110]
  PIN wupper[111]
    DIRECTION INPUT ;
    USE SIGNAL ;
    PORT
      LAYER M4 ;
        RECT  0.054 53.904 0.138 53.928 ;
    END
  END wupper[111]
  PIN wupper[112]
    DIRECTION INPUT ;
    USE SIGNAL ;
    PORT
      LAYER M4 ;
        RECT  0.054 54.096 0.138 54.12 ;
    END
  END wupper[112]
  PIN wupper[113]
    DIRECTION INPUT ;
    USE SIGNAL ;
    PORT
      LAYER M4 ;
        RECT  0.054 54.336 0.138 54.36 ;
    END
  END wupper[113]
  PIN wupper[114]
    DIRECTION INPUT ;
    USE SIGNAL ;
    PORT
      LAYER M4 ;
        RECT  0.054 54.528 0.138 54.552 ;
    END
  END wupper[114]
  PIN wupper[115]
    DIRECTION INPUT ;
    USE SIGNAL ;
    PORT
      LAYER M4 ;
        RECT  0.054 54.72 0.138 54.744 ;
    END
  END wupper[115]
  PIN wupper[116]
    DIRECTION INPUT ;
    USE SIGNAL ;
    PORT
      LAYER M4 ;
        RECT  0.054 54.912 0.138 54.936 ;
    END
  END wupper[116]
  PIN wupper[117]
    DIRECTION INPUT ;
    USE SIGNAL ;
    PORT
      LAYER M4 ;
        RECT  0.054 55.104 0.138 55.128 ;
    END
  END wupper[117]
  PIN wupper[118]
    DIRECTION INPUT ;
    USE SIGNAL ;
    PORT
      LAYER M4 ;
        RECT  0.054 55.344 0.138 55.368 ;
    END
  END wupper[118]
  PIN wupper[119]
    DIRECTION INPUT ;
    USE SIGNAL ;
    PORT
      LAYER M4 ;
        RECT  0.054 55.536 0.138 55.56 ;
    END
  END wupper[119]
  PIN wupper[11]
    DIRECTION INPUT ;
    USE SIGNAL ;
    PORT
      LAYER M4 ;
        RECT  0.054 33.6 0.138 33.624 ;
    END
  END wupper[11]
  PIN wupper[120]
    DIRECTION INPUT ;
    USE SIGNAL ;
    PORT
      LAYER M4 ;
        RECT  0.054 55.728 0.138 55.752 ;
    END
  END wupper[120]
  PIN wupper[121]
    DIRECTION INPUT ;
    USE SIGNAL ;
    PORT
      LAYER M4 ;
        RECT  0.054 55.92 0.138 55.944 ;
    END
  END wupper[121]
  PIN wupper[122]
    DIRECTION INPUT ;
    USE SIGNAL ;
    PORT
      LAYER M4 ;
        RECT  0.054 56.16 0.138 56.184 ;
    END
  END wupper[122]
  PIN wupper[123]
    DIRECTION INPUT ;
    USE SIGNAL ;
    PORT
      LAYER M4 ;
        RECT  0.054 56.352 0.138 56.376 ;
    END
  END wupper[123]
  PIN wupper[124]
    DIRECTION INPUT ;
    USE SIGNAL ;
    PORT
      LAYER M4 ;
        RECT  0.054 56.544 0.138 56.568 ;
    END
  END wupper[124]
  PIN wupper[125]
    DIRECTION INPUT ;
    USE SIGNAL ;
    PORT
      LAYER M4 ;
        RECT  0.054 56.736 0.138 56.76 ;
    END
  END wupper[125]
  PIN wupper[126]
    DIRECTION INPUT ;
    USE SIGNAL ;
    PORT
      LAYER M4 ;
        RECT  0.054 56.928 0.138 56.952 ;
    END
  END wupper[126]
  PIN wupper[127]
    DIRECTION INPUT ;
    USE SIGNAL ;
    PORT
      LAYER M4 ;
        RECT  0.054 57.168 0.138 57.192 ;
    END
  END wupper[127]
  PIN wupper[12]
    DIRECTION INPUT ;
    USE SIGNAL ;
    PORT
      LAYER M4 ;
        RECT  0.054 33.792 0.138 33.816 ;
    END
  END wupper[12]
  PIN wupper[13]
    DIRECTION INPUT ;
    USE SIGNAL ;
    PORT
      LAYER M4 ;
        RECT  0.054 34.032 0.138 34.056 ;
    END
  END wupper[13]
  PIN wupper[14]
    DIRECTION INPUT ;
    USE SIGNAL ;
    PORT
      LAYER M4 ;
        RECT  0.054 34.224 0.138 34.248 ;
    END
  END wupper[14]
  PIN wupper[15]
    DIRECTION INPUT ;
    USE SIGNAL ;
    PORT
      LAYER M4 ;
        RECT  0.054 34.416 0.138 34.44 ;
    END
  END wupper[15]
  PIN wupper[16]
    DIRECTION INPUT ;
    USE SIGNAL ;
    PORT
      LAYER M4 ;
        RECT  0.054 34.608 0.138 34.632 ;
    END
  END wupper[16]
  PIN wupper[17]
    DIRECTION INPUT ;
    USE SIGNAL ;
    PORT
      LAYER M4 ;
        RECT  0.054 34.848 0.138 34.872 ;
    END
  END wupper[17]
  PIN wupper[18]
    DIRECTION INPUT ;
    USE SIGNAL ;
    PORT
      LAYER M4 ;
        RECT  0.054 35.04 0.138 35.064 ;
    END
  END wupper[18]
  PIN wupper[19]
    DIRECTION INPUT ;
    USE SIGNAL ;
    PORT
      LAYER M4 ;
        RECT  0.054 35.232 0.138 35.256 ;
    END
  END wupper[19]
  PIN wupper[1]
    DIRECTION INPUT ;
    USE SIGNAL ;
    PORT
      LAYER M4 ;
        RECT  0.054 31.584 0.138 31.608 ;
    END
  END wupper[1]
  PIN wupper[20]
    DIRECTION INPUT ;
    USE SIGNAL ;
    PORT
      LAYER M4 ;
        RECT  0.054 35.424 0.138 35.448 ;
    END
  END wupper[20]
  PIN wupper[21]
    DIRECTION INPUT ;
    USE SIGNAL ;
    PORT
      LAYER M4 ;
        RECT  0.054 35.616 0.138 35.64 ;
    END
  END wupper[21]
  PIN wupper[22]
    DIRECTION INPUT ;
    USE SIGNAL ;
    PORT
      LAYER M4 ;
        RECT  0.054 35.856 0.138 35.88 ;
    END
  END wupper[22]
  PIN wupper[23]
    DIRECTION INPUT ;
    USE SIGNAL ;
    PORT
      LAYER M4 ;
        RECT  0.054 36.048 0.138 36.072 ;
    END
  END wupper[23]
  PIN wupper[24]
    DIRECTION INPUT ;
    USE SIGNAL ;
    PORT
      LAYER M4 ;
        RECT  0.054 36.24 0.138 36.264 ;
    END
  END wupper[24]
  PIN wupper[25]
    DIRECTION INPUT ;
    USE SIGNAL ;
    PORT
      LAYER M4 ;
        RECT  0.054 36.432 0.138 36.456 ;
    END
  END wupper[25]
  PIN wupper[26]
    DIRECTION INPUT ;
    USE SIGNAL ;
    PORT
      LAYER M4 ;
        RECT  0.054 36.672 0.138 36.696 ;
    END
  END wupper[26]
  PIN wupper[27]
    DIRECTION INPUT ;
    USE SIGNAL ;
    PORT
      LAYER M4 ;
        RECT  0.054 36.864 0.138 36.888 ;
    END
  END wupper[27]
  PIN wupper[28]
    DIRECTION INPUT ;
    USE SIGNAL ;
    PORT
      LAYER M4 ;
        RECT  0.054 37.056 0.138 37.08 ;
    END
  END wupper[28]
  PIN wupper[29]
    DIRECTION INPUT ;
    USE SIGNAL ;
    PORT
      LAYER M4 ;
        RECT  0.054 37.248 0.138 37.272 ;
    END
  END wupper[29]
  PIN wupper[2]
    DIRECTION INPUT ;
    USE SIGNAL ;
    PORT
      LAYER M4 ;
        RECT  0.054 31.776 0.138 31.8 ;
    END
  END wupper[2]
  PIN wupper[30]
    DIRECTION INPUT ;
    USE SIGNAL ;
    PORT
      LAYER M4 ;
        RECT  0.054 37.44 0.138 37.464 ;
    END
  END wupper[30]
  PIN wupper[31]
    DIRECTION INPUT ;
    USE SIGNAL ;
    PORT
      LAYER M4 ;
        RECT  0.054 37.68 0.138 37.704 ;
    END
  END wupper[31]
  PIN wupper[32]
    DIRECTION INPUT ;
    USE SIGNAL ;
    PORT
      LAYER M4 ;
        RECT  0.054 37.872 0.138 37.896 ;
    END
  END wupper[32]
  PIN wupper[33]
    DIRECTION INPUT ;
    USE SIGNAL ;
    PORT
      LAYER M4 ;
        RECT  0.054 38.064 0.138 38.088 ;
    END
  END wupper[33]
  PIN wupper[34]
    DIRECTION INPUT ;
    USE SIGNAL ;
    PORT
      LAYER M4 ;
        RECT  0.054 38.256 0.138 38.28 ;
    END
  END wupper[34]
  PIN wupper[35]
    DIRECTION INPUT ;
    USE SIGNAL ;
    PORT
      LAYER M4 ;
        RECT  0.054 38.496 0.138 38.52 ;
    END
  END wupper[35]
  PIN wupper[36]
    DIRECTION INPUT ;
    USE SIGNAL ;
    PORT
      LAYER M4 ;
        RECT  0.054 38.688 0.138 38.712 ;
    END
  END wupper[36]
  PIN wupper[37]
    DIRECTION INPUT ;
    USE SIGNAL ;
    PORT
      LAYER M4 ;
        RECT  0.054 38.88 0.138 38.904 ;
    END
  END wupper[37]
  PIN wupper[38]
    DIRECTION INPUT ;
    USE SIGNAL ;
    PORT
      LAYER M4 ;
        RECT  0.054 39.072 0.138 39.096 ;
    END
  END wupper[38]
  PIN wupper[39]
    DIRECTION INPUT ;
    USE SIGNAL ;
    PORT
      LAYER M4 ;
        RECT  0.054 39.312 0.138 39.336 ;
    END
  END wupper[39]
  PIN wupper[3]
    DIRECTION INPUT ;
    USE SIGNAL ;
    PORT
      LAYER M4 ;
        RECT  0.054 31.968 0.138 31.992 ;
    END
  END wupper[3]
  PIN wupper[40]
    DIRECTION INPUT ;
    USE SIGNAL ;
    PORT
      LAYER M4 ;
        RECT  0.054 39.504 0.138 39.528 ;
    END
  END wupper[40]
  PIN wupper[41]
    DIRECTION INPUT ;
    USE SIGNAL ;
    PORT
      LAYER M4 ;
        RECT  0.054 39.696 0.138 39.72 ;
    END
  END wupper[41]
  PIN wupper[42]
    DIRECTION INPUT ;
    USE SIGNAL ;
    PORT
      LAYER M4 ;
        RECT  0.054 39.888 0.138 39.912 ;
    END
  END wupper[42]
  PIN wupper[43]
    DIRECTION INPUT ;
    USE SIGNAL ;
    PORT
      LAYER M4 ;
        RECT  0.054 40.08 0.138 40.104 ;
    END
  END wupper[43]
  PIN wupper[44]
    DIRECTION INPUT ;
    USE SIGNAL ;
    PORT
      LAYER M4 ;
        RECT  0.054 40.32 0.138 40.344 ;
    END
  END wupper[44]
  PIN wupper[45]
    DIRECTION INPUT ;
    USE SIGNAL ;
    PORT
      LAYER M4 ;
        RECT  0.054 40.512 0.138 40.536 ;
    END
  END wupper[45]
  PIN wupper[46]
    DIRECTION INPUT ;
    USE SIGNAL ;
    PORT
      LAYER M4 ;
        RECT  0.054 40.704 0.138 40.728 ;
    END
  END wupper[46]
  PIN wupper[47]
    DIRECTION INPUT ;
    USE SIGNAL ;
    PORT
      LAYER M4 ;
        RECT  0.054 40.896 0.138 40.92 ;
    END
  END wupper[47]
  PIN wupper[48]
    DIRECTION INPUT ;
    USE SIGNAL ;
    PORT
      LAYER M4 ;
        RECT  0.054 41.136 0.138 41.16 ;
    END
  END wupper[48]
  PIN wupper[49]
    DIRECTION INPUT ;
    USE SIGNAL ;
    PORT
      LAYER M4 ;
        RECT  0.054 41.328 0.138 41.352 ;
    END
  END wupper[49]
  PIN wupper[4]
    DIRECTION INPUT ;
    USE SIGNAL ;
    PORT
      LAYER M4 ;
        RECT  0.054 32.208 0.138 32.232 ;
    END
  END wupper[4]
  PIN wupper[50]
    DIRECTION INPUT ;
    USE SIGNAL ;
    PORT
      LAYER M4 ;
        RECT  0.054 41.52 0.138 41.544 ;
    END
  END wupper[50]
  PIN wupper[51]
    DIRECTION INPUT ;
    USE SIGNAL ;
    PORT
      LAYER M4 ;
        RECT  0.054 41.712 0.138 41.736 ;
    END
  END wupper[51]
  PIN wupper[52]
    DIRECTION INPUT ;
    USE SIGNAL ;
    PORT
      LAYER M4 ;
        RECT  0.054 41.952 0.138 41.976 ;
    END
  END wupper[52]
  PIN wupper[53]
    DIRECTION INPUT ;
    USE SIGNAL ;
    PORT
      LAYER M4 ;
        RECT  0.054 42.144 0.138 42.168 ;
    END
  END wupper[53]
  PIN wupper[54]
    DIRECTION INPUT ;
    USE SIGNAL ;
    PORT
      LAYER M4 ;
        RECT  0.054 42.336 0.138 42.36 ;
    END
  END wupper[54]
  PIN wupper[55]
    DIRECTION INPUT ;
    USE SIGNAL ;
    PORT
      LAYER M4 ;
        RECT  0.054 42.528 0.138 42.552 ;
    END
  END wupper[55]
  PIN wupper[56]
    DIRECTION INPUT ;
    USE SIGNAL ;
    PORT
      LAYER M4 ;
        RECT  0.054 42.72 0.138 42.744 ;
    END
  END wupper[56]
  PIN wupper[57]
    DIRECTION INPUT ;
    USE SIGNAL ;
    PORT
      LAYER M4 ;
        RECT  0.054 42.96 0.138 42.984 ;
    END
  END wupper[57]
  PIN wupper[58]
    DIRECTION INPUT ;
    USE SIGNAL ;
    PORT
      LAYER M4 ;
        RECT  0.054 43.152 0.138 43.176 ;
    END
  END wupper[58]
  PIN wupper[59]
    DIRECTION INPUT ;
    USE SIGNAL ;
    PORT
      LAYER M4 ;
        RECT  0.054 43.344 0.138 43.368 ;
    END
  END wupper[59]
  PIN wupper[5]
    DIRECTION INPUT ;
    USE SIGNAL ;
    PORT
      LAYER M4 ;
        RECT  0.054 32.4 0.138 32.424 ;
    END
  END wupper[5]
  PIN wupper[60]
    DIRECTION INPUT ;
    USE SIGNAL ;
    PORT
      LAYER M4 ;
        RECT  0.054 43.536 0.138 43.56 ;
    END
  END wupper[60]
  PIN wupper[61]
    DIRECTION INPUT ;
    USE SIGNAL ;
    PORT
      LAYER M4 ;
        RECT  0.054 43.776 0.138 43.8 ;
    END
  END wupper[61]
  PIN wupper[62]
    DIRECTION INPUT ;
    USE SIGNAL ;
    PORT
      LAYER M4 ;
        RECT  0.054 43.968 0.138 43.992 ;
    END
  END wupper[62]
  PIN wupper[63]
    DIRECTION INPUT ;
    USE SIGNAL ;
    PORT
      LAYER M4 ;
        RECT  0.054 44.16 0.138 44.184 ;
    END
  END wupper[63]
  PIN wupper[64]
    DIRECTION INPUT ;
    USE SIGNAL ;
    PORT
      LAYER M4 ;
        RECT  0.054 44.352 0.138 44.376 ;
    END
  END wupper[64]
  PIN wupper[65]
    DIRECTION INPUT ;
    USE SIGNAL ;
    PORT
      LAYER M4 ;
        RECT  0.054 44.592 0.138 44.616 ;
    END
  END wupper[65]
  PIN wupper[66]
    DIRECTION INPUT ;
    USE SIGNAL ;
    PORT
      LAYER M4 ;
        RECT  0.054 44.784 0.138 44.808 ;
    END
  END wupper[66]
  PIN wupper[67]
    DIRECTION INPUT ;
    USE SIGNAL ;
    PORT
      LAYER M4 ;
        RECT  0.054 44.976 0.138 45 ;
    END
  END wupper[67]
  PIN wupper[68]
    DIRECTION INPUT ;
    USE SIGNAL ;
    PORT
      LAYER M4 ;
        RECT  0.054 45.168 0.138 45.192 ;
    END
  END wupper[68]
  PIN wupper[69]
    DIRECTION INPUT ;
    USE SIGNAL ;
    PORT
      LAYER M4 ;
        RECT  0.054 45.36 0.138 45.384 ;
    END
  END wupper[69]
  PIN wupper[6]
    DIRECTION INPUT ;
    USE SIGNAL ;
    PORT
      LAYER M4 ;
        RECT  0.054 32.592 0.138 32.616 ;
    END
  END wupper[6]
  PIN wupper[70]
    DIRECTION INPUT ;
    USE SIGNAL ;
    PORT
      LAYER M4 ;
        RECT  0.054 45.6 0.138 45.624 ;
    END
  END wupper[70]
  PIN wupper[71]
    DIRECTION INPUT ;
    USE SIGNAL ;
    PORT
      LAYER M4 ;
        RECT  0.054 45.792 0.138 45.816 ;
    END
  END wupper[71]
  PIN wupper[72]
    DIRECTION INPUT ;
    USE SIGNAL ;
    PORT
      LAYER M4 ;
        RECT  0.054 45.984 0.138 46.008 ;
    END
  END wupper[72]
  PIN wupper[73]
    DIRECTION INPUT ;
    USE SIGNAL ;
    PORT
      LAYER M4 ;
        RECT  0.054 46.176 0.138 46.2 ;
    END
  END wupper[73]
  PIN wupper[74]
    DIRECTION INPUT ;
    USE SIGNAL ;
    PORT
      LAYER M4 ;
        RECT  0.054 46.416 0.138 46.44 ;
    END
  END wupper[74]
  PIN wupper[75]
    DIRECTION INPUT ;
    USE SIGNAL ;
    PORT
      LAYER M4 ;
        RECT  0.054 46.608 0.138 46.632 ;
    END
  END wupper[75]
  PIN wupper[76]
    DIRECTION INPUT ;
    USE SIGNAL ;
    PORT
      LAYER M4 ;
        RECT  0.054 46.8 0.138 46.824 ;
    END
  END wupper[76]
  PIN wupper[77]
    DIRECTION INPUT ;
    USE SIGNAL ;
    PORT
      LAYER M4 ;
        RECT  0.054 46.992 0.138 47.016 ;
    END
  END wupper[77]
  PIN wupper[78]
    DIRECTION INPUT ;
    USE SIGNAL ;
    PORT
      LAYER M4 ;
        RECT  0.054 47.184 0.138 47.208 ;
    END
  END wupper[78]
  PIN wupper[79]
    DIRECTION INPUT ;
    USE SIGNAL ;
    PORT
      LAYER M4 ;
        RECT  0.054 47.424 0.138 47.448 ;
    END
  END wupper[79]
  PIN wupper[7]
    DIRECTION INPUT ;
    USE SIGNAL ;
    PORT
      LAYER M4 ;
        RECT  0.054 32.784 0.138 32.808 ;
    END
  END wupper[7]
  PIN wupper[80]
    DIRECTION INPUT ;
    USE SIGNAL ;
    PORT
      LAYER M4 ;
        RECT  0.054 47.616 0.138 47.64 ;
    END
  END wupper[80]
  PIN wupper[81]
    DIRECTION INPUT ;
    USE SIGNAL ;
    PORT
      LAYER M4 ;
        RECT  0.054 47.808 0.138 47.832 ;
    END
  END wupper[81]
  PIN wupper[82]
    DIRECTION INPUT ;
    USE SIGNAL ;
    PORT
      LAYER M4 ;
        RECT  0.054 48 0.138 48.024 ;
    END
  END wupper[82]
  PIN wupper[83]
    DIRECTION INPUT ;
    USE SIGNAL ;
    PORT
      LAYER M4 ;
        RECT  0.054 48.24 0.138 48.264 ;
    END
  END wupper[83]
  PIN wupper[84]
    DIRECTION INPUT ;
    USE SIGNAL ;
    PORT
      LAYER M4 ;
        RECT  0.054 48.432 0.138 48.456 ;
    END
  END wupper[84]
  PIN wupper[85]
    DIRECTION INPUT ;
    USE SIGNAL ;
    PORT
      LAYER M4 ;
        RECT  0.054 48.624 0.138 48.648 ;
    END
  END wupper[85]
  PIN wupper[86]
    DIRECTION INPUT ;
    USE SIGNAL ;
    PORT
      LAYER M4 ;
        RECT  0.054 48.816 0.138 48.84 ;
    END
  END wupper[86]
  PIN wupper[87]
    DIRECTION INPUT ;
    USE SIGNAL ;
    PORT
      LAYER M4 ;
        RECT  0.054 49.056 0.138 49.08 ;
    END
  END wupper[87]
  PIN wupper[88]
    DIRECTION INPUT ;
    USE SIGNAL ;
    PORT
      LAYER M4 ;
        RECT  0.054 49.248 0.138 49.272 ;
    END
  END wupper[88]
  PIN wupper[89]
    DIRECTION INPUT ;
    USE SIGNAL ;
    PORT
      LAYER M4 ;
        RECT  0.054 49.44 0.138 49.464 ;
    END
  END wupper[89]
  PIN wupper[8]
    DIRECTION INPUT ;
    USE SIGNAL ;
    PORT
      LAYER M4 ;
        RECT  0.054 32.976 0.138 33 ;
    END
  END wupper[8]
  PIN wupper[90]
    DIRECTION INPUT ;
    USE SIGNAL ;
    PORT
      LAYER M4 ;
        RECT  0.054 49.632 0.138 49.656 ;
    END
  END wupper[90]
  PIN wupper[91]
    DIRECTION INPUT ;
    USE SIGNAL ;
    PORT
      LAYER M4 ;
        RECT  0.054 49.824 0.138 49.848 ;
    END
  END wupper[91]
  PIN wupper[92]
    DIRECTION INPUT ;
    USE SIGNAL ;
    PORT
      LAYER M4 ;
        RECT  0.054 50.064 0.138 50.088 ;
    END
  END wupper[92]
  PIN wupper[93]
    DIRECTION INPUT ;
    USE SIGNAL ;
    PORT
      LAYER M4 ;
        RECT  0.054 50.256 0.138 50.28 ;
    END
  END wupper[93]
  PIN wupper[94]
    DIRECTION INPUT ;
    USE SIGNAL ;
    PORT
      LAYER M4 ;
        RECT  0.054 50.448 0.138 50.472 ;
    END
  END wupper[94]
  PIN wupper[95]
    DIRECTION INPUT ;
    USE SIGNAL ;
    PORT
      LAYER M4 ;
        RECT  0.054 50.64 0.138 50.664 ;
    END
  END wupper[95]
  PIN wupper[96]
    DIRECTION INPUT ;
    USE SIGNAL ;
    PORT
      LAYER M4 ;
        RECT  0.054 50.88 0.138 50.904 ;
    END
  END wupper[96]
  PIN wupper[97]
    DIRECTION INPUT ;
    USE SIGNAL ;
    PORT
      LAYER M4 ;
        RECT  0.054 51.072 0.138 51.096 ;
    END
  END wupper[97]
  PIN wupper[98]
    DIRECTION INPUT ;
    USE SIGNAL ;
    PORT
      LAYER M4 ;
        RECT  0.054 51.264 0.138 51.288 ;
    END
  END wupper[98]
  PIN wupper[99]
    DIRECTION INPUT ;
    USE SIGNAL ;
    PORT
      LAYER M4 ;
        RECT  0.054 51.456 0.138 51.48 ;
    END
  END wupper[99]
  PIN wupper[9]
    DIRECTION INPUT ;
    USE SIGNAL ;
    PORT
      LAYER M4 ;
        RECT  0.054 33.216 0.138 33.24 ;
    END
  END wupper[9]
  PIN x[0]
    DIRECTION INPUT ;
    USE SIGNAL ;
    PORT
      LAYER M4 ;
        RECT  0.054 5.424 0.138 5.448 ;
    END
  END x[0]
  PIN x[100]
    DIRECTION INPUT ;
    USE SIGNAL ;
    PORT
      LAYER M4 ;
        RECT  0.054 25.68 0.138 25.704 ;
    END
  END x[100]
  PIN x[101]
    DIRECTION INPUT ;
    USE SIGNAL ;
    PORT
      LAYER M4 ;
        RECT  0.054 25.872 0.138 25.896 ;
    END
  END x[101]
  PIN x[102]
    DIRECTION INPUT ;
    USE SIGNAL ;
    PORT
      LAYER M4 ;
        RECT  0.054 26.112 0.138 26.136 ;
    END
  END x[102]
  PIN x[103]
    DIRECTION INPUT ;
    USE SIGNAL ;
    PORT
      LAYER M4 ;
        RECT  0.054 26.304 0.138 26.328 ;
    END
  END x[103]
  PIN x[104]
    DIRECTION INPUT ;
    USE SIGNAL ;
    PORT
      LAYER M4 ;
        RECT  0.054 26.496 0.138 26.52 ;
    END
  END x[104]
  PIN x[105]
    DIRECTION INPUT ;
    USE SIGNAL ;
    PORT
      LAYER M4 ;
        RECT  0.054 26.688 0.138 26.712 ;
    END
  END x[105]
  PIN x[106]
    DIRECTION INPUT ;
    USE SIGNAL ;
    PORT
      LAYER M4 ;
        RECT  0.054 26.928 0.138 26.952 ;
    END
  END x[106]
  PIN x[107]
    DIRECTION INPUT ;
    USE SIGNAL ;
    PORT
      LAYER M4 ;
        RECT  0.054 27.12 0.138 27.144 ;
    END
  END x[107]
  PIN x[108]
    DIRECTION INPUT ;
    USE SIGNAL ;
    PORT
      LAYER M4 ;
        RECT  0.054 27.312 0.138 27.336 ;
    END
  END x[108]
  PIN x[109]
    DIRECTION INPUT ;
    USE SIGNAL ;
    PORT
      LAYER M4 ;
        RECT  0.054 27.504 0.138 27.528 ;
    END
  END x[109]
  PIN x[10]
    DIRECTION INPUT ;
    USE SIGNAL ;
    PORT
      LAYER M4 ;
        RECT  0.054 7.44 0.138 7.464 ;
    END
  END x[10]
  PIN x[110]
    DIRECTION INPUT ;
    USE SIGNAL ;
    PORT
      LAYER M4 ;
        RECT  0.054 27.696 0.138 27.72 ;
    END
  END x[110]
  PIN x[111]
    DIRECTION INPUT ;
    USE SIGNAL ;
    PORT
      LAYER M4 ;
        RECT  0.054 27.936 0.138 27.96 ;
    END
  END x[111]
  PIN x[112]
    DIRECTION INPUT ;
    USE SIGNAL ;
    PORT
      LAYER M4 ;
        RECT  0.054 28.128 0.138 28.152 ;
    END
  END x[112]
  PIN x[113]
    DIRECTION INPUT ;
    USE SIGNAL ;
    PORT
      LAYER M4 ;
        RECT  0.054 28.32 0.138 28.344 ;
    END
  END x[113]
  PIN x[114]
    DIRECTION INPUT ;
    USE SIGNAL ;
    PORT
      LAYER M4 ;
        RECT  0.054 28.512 0.138 28.536 ;
    END
  END x[114]
  PIN x[115]
    DIRECTION INPUT ;
    USE SIGNAL ;
    PORT
      LAYER M4 ;
        RECT  0.054 28.752 0.138 28.776 ;
    END
  END x[115]
  PIN x[116]
    DIRECTION INPUT ;
    USE SIGNAL ;
    PORT
      LAYER M4 ;
        RECT  0.054 28.944 0.138 28.968 ;
    END
  END x[116]
  PIN x[117]
    DIRECTION INPUT ;
    USE SIGNAL ;
    PORT
      LAYER M4 ;
        RECT  0.054 29.136 0.138 29.16 ;
    END
  END x[117]
  PIN x[118]
    DIRECTION INPUT ;
    USE SIGNAL ;
    PORT
      LAYER M4 ;
        RECT  0.054 29.328 0.138 29.352 ;
    END
  END x[118]
  PIN x[119]
    DIRECTION INPUT ;
    USE SIGNAL ;
    PORT
      LAYER M4 ;
        RECT  0.054 29.568 0.138 29.592 ;
    END
  END x[119]
  PIN x[11]
    DIRECTION INPUT ;
    USE SIGNAL ;
    PORT
      LAYER M4 ;
        RECT  0.054 7.632 0.138 7.656 ;
    END
  END x[11]
  PIN x[120]
    DIRECTION INPUT ;
    USE SIGNAL ;
    PORT
      LAYER M4 ;
        RECT  0.054 29.76 0.138 29.784 ;
    END
  END x[120]
  PIN x[121]
    DIRECTION INPUT ;
    USE SIGNAL ;
    PORT
      LAYER M4 ;
        RECT  0.054 29.952 0.138 29.976 ;
    END
  END x[121]
  PIN x[122]
    DIRECTION INPUT ;
    USE SIGNAL ;
    PORT
      LAYER M4 ;
        RECT  0.054 30.144 0.138 30.168 ;
    END
  END x[122]
  PIN x[123]
    DIRECTION INPUT ;
    USE SIGNAL ;
    PORT
      LAYER M4 ;
        RECT  0.054 30.336 0.138 30.36 ;
    END
  END x[123]
  PIN x[124]
    DIRECTION INPUT ;
    USE SIGNAL ;
    PORT
      LAYER M4 ;
        RECT  0.054 30.576 0.138 30.6 ;
    END
  END x[124]
  PIN x[125]
    DIRECTION INPUT ;
    USE SIGNAL ;
    PORT
      LAYER M4 ;
        RECT  0.054 30.768 0.138 30.792 ;
    END
  END x[125]
  PIN x[126]
    DIRECTION INPUT ;
    USE SIGNAL ;
    PORT
      LAYER M4 ;
        RECT  0.054 30.96 0.138 30.984 ;
    END
  END x[126]
  PIN x[127]
    DIRECTION INPUT ;
    USE SIGNAL ;
    PORT
      LAYER M4 ;
        RECT  0.054 31.152 0.138 31.176 ;
    END
  END x[127]
  PIN x[12]
    DIRECTION INPUT ;
    USE SIGNAL ;
    PORT
      LAYER M4 ;
        RECT  0.054 7.824 0.138 7.848 ;
    END
  END x[12]
  PIN x[13]
    DIRECTION INPUT ;
    USE SIGNAL ;
    PORT
      LAYER M4 ;
        RECT  0.054 8.016 0.138 8.04 ;
    END
  END x[13]
  PIN x[14]
    DIRECTION INPUT ;
    USE SIGNAL ;
    PORT
      LAYER M4 ;
        RECT  0.054 8.208 0.138 8.232 ;
    END
  END x[14]
  PIN x[15]
    DIRECTION INPUT ;
    USE SIGNAL ;
    PORT
      LAYER M4 ;
        RECT  0.054 8.448 0.138 8.472 ;
    END
  END x[15]
  PIN x[16]
    DIRECTION INPUT ;
    USE SIGNAL ;
    PORT
      LAYER M4 ;
        RECT  0.054 8.64 0.138 8.664 ;
    END
  END x[16]
  PIN x[17]
    DIRECTION INPUT ;
    USE SIGNAL ;
    PORT
      LAYER M4 ;
        RECT  0.054 8.832 0.138 8.856 ;
    END
  END x[17]
  PIN x[18]
    DIRECTION INPUT ;
    USE SIGNAL ;
    PORT
      LAYER M4 ;
        RECT  0.054 9.024 0.138 9.048 ;
    END
  END x[18]
  PIN x[19]
    DIRECTION INPUT ;
    USE SIGNAL ;
    PORT
      LAYER M4 ;
        RECT  0.054 9.264 0.138 9.288 ;
    END
  END x[19]
  PIN x[1]
    DIRECTION INPUT ;
    USE SIGNAL ;
    PORT
      LAYER M4 ;
        RECT  0.054 5.568 0.138 5.592 ;
    END
  END x[1]
  PIN x[20]
    DIRECTION INPUT ;
    USE SIGNAL ;
    PORT
      LAYER M4 ;
        RECT  0.054 9.456 0.138 9.48 ;
    END
  END x[20]
  PIN x[21]
    DIRECTION INPUT ;
    USE SIGNAL ;
    PORT
      LAYER M4 ;
        RECT  0.054 9.648 0.138 9.672 ;
    END
  END x[21]
  PIN x[22]
    DIRECTION INPUT ;
    USE SIGNAL ;
    PORT
      LAYER M4 ;
        RECT  0.054 9.84 0.138 9.864 ;
    END
  END x[22]
  PIN x[23]
    DIRECTION INPUT ;
    USE SIGNAL ;
    PORT
      LAYER M4 ;
        RECT  0.054 10.08 0.138 10.104 ;
    END
  END x[23]
  PIN x[24]
    DIRECTION INPUT ;
    USE SIGNAL ;
    PORT
      LAYER M4 ;
        RECT  0.054 10.272 0.138 10.296 ;
    END
  END x[24]
  PIN x[25]
    DIRECTION INPUT ;
    USE SIGNAL ;
    PORT
      LAYER M4 ;
        RECT  0.054 10.464 0.138 10.488 ;
    END
  END x[25]
  PIN x[26]
    DIRECTION INPUT ;
    USE SIGNAL ;
    PORT
      LAYER M4 ;
        RECT  0.054 10.656 0.138 10.68 ;
    END
  END x[26]
  PIN x[27]
    DIRECTION INPUT ;
    USE SIGNAL ;
    PORT
      LAYER M4 ;
        RECT  0.054 10.848 0.138 10.872 ;
    END
  END x[27]
  PIN x[28]
    DIRECTION INPUT ;
    USE SIGNAL ;
    PORT
      LAYER M4 ;
        RECT  0.054 11.088 0.138 11.112 ;
    END
  END x[28]
  PIN x[29]
    DIRECTION INPUT ;
    USE SIGNAL ;
    PORT
      LAYER M4 ;
        RECT  0.054 11.28 0.138 11.304 ;
    END
  END x[29]
  PIN x[2]
    DIRECTION INPUT ;
    USE SIGNAL ;
    PORT
      LAYER M4 ;
        RECT  0.054 5.808 0.138 5.832 ;
    END
  END x[2]
  PIN x[30]
    DIRECTION INPUT ;
    USE SIGNAL ;
    PORT
      LAYER M4 ;
        RECT  0.054 11.472 0.138 11.496 ;
    END
  END x[30]
  PIN x[31]
    DIRECTION INPUT ;
    USE SIGNAL ;
    PORT
      LAYER M4 ;
        RECT  0.054 11.664 0.138 11.688 ;
    END
  END x[31]
  PIN x[32]
    DIRECTION INPUT ;
    USE SIGNAL ;
    PORT
      LAYER M4 ;
        RECT  0.054 11.904 0.138 11.928 ;
    END
  END x[32]
  PIN x[33]
    DIRECTION INPUT ;
    USE SIGNAL ;
    PORT
      LAYER M4 ;
        RECT  0.054 12.096 0.138 12.12 ;
    END
  END x[33]
  PIN x[34]
    DIRECTION INPUT ;
    USE SIGNAL ;
    PORT
      LAYER M4 ;
        RECT  0.054 12.288 0.138 12.312 ;
    END
  END x[34]
  PIN x[35]
    DIRECTION INPUT ;
    USE SIGNAL ;
    PORT
      LAYER M4 ;
        RECT  0.054 12.48 0.138 12.504 ;
    END
  END x[35]
  PIN x[36]
    DIRECTION INPUT ;
    USE SIGNAL ;
    PORT
      LAYER M4 ;
        RECT  0.054 12.72 0.138 12.744 ;
    END
  END x[36]
  PIN x[37]
    DIRECTION INPUT ;
    USE SIGNAL ;
    PORT
      LAYER M4 ;
        RECT  0.054 12.912 0.138 12.936 ;
    END
  END x[37]
  PIN x[38]
    DIRECTION INPUT ;
    USE SIGNAL ;
    PORT
      LAYER M4 ;
        RECT  0.054 13.104 0.138 13.128 ;
    END
  END x[38]
  PIN x[39]
    DIRECTION INPUT ;
    USE SIGNAL ;
    PORT
      LAYER M4 ;
        RECT  0.054 13.296 0.138 13.32 ;
    END
  END x[39]
  PIN x[3]
    DIRECTION INPUT ;
    USE SIGNAL ;
    PORT
      LAYER M4 ;
        RECT  0.054 6 0.138 6.024 ;
    END
  END x[3]
  PIN x[40]
    DIRECTION INPUT ;
    USE SIGNAL ;
    PORT
      LAYER M4 ;
        RECT  0.054 13.488 0.138 13.512 ;
    END
  END x[40]
  PIN x[41]
    DIRECTION INPUT ;
    USE SIGNAL ;
    PORT
      LAYER M4 ;
        RECT  0.054 13.728 0.138 13.752 ;
    END
  END x[41]
  PIN x[42]
    DIRECTION INPUT ;
    USE SIGNAL ;
    PORT
      LAYER M4 ;
        RECT  0.054 13.92 0.138 13.944 ;
    END
  END x[42]
  PIN x[43]
    DIRECTION INPUT ;
    USE SIGNAL ;
    PORT
      LAYER M4 ;
        RECT  0.054 14.112 0.138 14.136 ;
    END
  END x[43]
  PIN x[44]
    DIRECTION INPUT ;
    USE SIGNAL ;
    PORT
      LAYER M4 ;
        RECT  0.054 14.304 0.138 14.328 ;
    END
  END x[44]
  PIN x[45]
    DIRECTION INPUT ;
    USE SIGNAL ;
    PORT
      LAYER M4 ;
        RECT  0.054 14.544 0.138 14.568 ;
    END
  END x[45]
  PIN x[46]
    DIRECTION INPUT ;
    USE SIGNAL ;
    PORT
      LAYER M4 ;
        RECT  0.054 14.736 0.138 14.76 ;
    END
  END x[46]
  PIN x[47]
    DIRECTION INPUT ;
    USE SIGNAL ;
    PORT
      LAYER M4 ;
        RECT  0.054 14.928 0.138 14.952 ;
    END
  END x[47]
  PIN x[48]
    DIRECTION INPUT ;
    USE SIGNAL ;
    PORT
      LAYER M4 ;
        RECT  0.054 15.12 0.138 15.144 ;
    END
  END x[48]
  PIN x[49]
    DIRECTION INPUT ;
    USE SIGNAL ;
    PORT
      LAYER M4 ;
        RECT  0.054 15.312 0.138 15.336 ;
    END
  END x[49]
  PIN x[4]
    DIRECTION INPUT ;
    USE SIGNAL ;
    PORT
      LAYER M4 ;
        RECT  0.054 6.192 0.138 6.216 ;
    END
  END x[4]
  PIN x[50]
    DIRECTION INPUT ;
    USE SIGNAL ;
    PORT
      LAYER M4 ;
        RECT  0.054 15.552 0.138 15.576 ;
    END
  END x[50]
  PIN x[51]
    DIRECTION INPUT ;
    USE SIGNAL ;
    PORT
      LAYER M4 ;
        RECT  0.054 15.744 0.138 15.768 ;
    END
  END x[51]
  PIN x[52]
    DIRECTION INPUT ;
    USE SIGNAL ;
    PORT
      LAYER M4 ;
        RECT  0.054 15.936 0.138 15.96 ;
    END
  END x[52]
  PIN x[53]
    DIRECTION INPUT ;
    USE SIGNAL ;
    PORT
      LAYER M4 ;
        RECT  0.054 16.128 0.138 16.152 ;
    END
  END x[53]
  PIN x[54]
    DIRECTION INPUT ;
    USE SIGNAL ;
    PORT
      LAYER M4 ;
        RECT  0.054 16.368 0.138 16.392 ;
    END
  END x[54]
  PIN x[55]
    DIRECTION INPUT ;
    USE SIGNAL ;
    PORT
      LAYER M4 ;
        RECT  0.054 16.56 0.138 16.584 ;
    END
  END x[55]
  PIN x[56]
    DIRECTION INPUT ;
    USE SIGNAL ;
    PORT
      LAYER M4 ;
        RECT  0.054 16.752 0.138 16.776 ;
    END
  END x[56]
  PIN x[57]
    DIRECTION INPUT ;
    USE SIGNAL ;
    PORT
      LAYER M4 ;
        RECT  0.054 16.944 0.138 16.968 ;
    END
  END x[57]
  PIN x[58]
    DIRECTION INPUT ;
    USE SIGNAL ;
    PORT
      LAYER M4 ;
        RECT  0.054 17.184 0.138 17.208 ;
    END
  END x[58]
  PIN x[59]
    DIRECTION INPUT ;
    USE SIGNAL ;
    PORT
      LAYER M4 ;
        RECT  0.054 17.376 0.138 17.4 ;
    END
  END x[59]
  PIN x[5]
    DIRECTION INPUT ;
    USE SIGNAL ;
    PORT
      LAYER M4 ;
        RECT  0.054 6.384 0.138 6.408 ;
    END
  END x[5]
  PIN x[60]
    DIRECTION INPUT ;
    USE SIGNAL ;
    PORT
      LAYER M4 ;
        RECT  0.054 17.568 0.138 17.592 ;
    END
  END x[60]
  PIN x[61]
    DIRECTION INPUT ;
    USE SIGNAL ;
    PORT
      LAYER M4 ;
        RECT  0.054 17.76 0.138 17.784 ;
    END
  END x[61]
  PIN x[62]
    DIRECTION INPUT ;
    USE SIGNAL ;
    PORT
      LAYER M4 ;
        RECT  0.054 17.952 0.138 17.976 ;
    END
  END x[62]
  PIN x[63]
    DIRECTION INPUT ;
    USE SIGNAL ;
    PORT
      LAYER M4 ;
        RECT  0.054 18.192 0.138 18.216 ;
    END
  END x[63]
  PIN x[64]
    DIRECTION INPUT ;
    USE SIGNAL ;
    PORT
      LAYER M4 ;
        RECT  0.054 18.384 0.138 18.408 ;
    END
  END x[64]
  PIN x[65]
    DIRECTION INPUT ;
    USE SIGNAL ;
    PORT
      LAYER M4 ;
        RECT  0.054 18.576 0.138 18.6 ;
    END
  END x[65]
  PIN x[66]
    DIRECTION INPUT ;
    USE SIGNAL ;
    PORT
      LAYER M4 ;
        RECT  0.054 18.768 0.138 18.792 ;
    END
  END x[66]
  PIN x[67]
    DIRECTION INPUT ;
    USE SIGNAL ;
    PORT
      LAYER M4 ;
        RECT  0.054 19.008 0.138 19.032 ;
    END
  END x[67]
  PIN x[68]
    DIRECTION INPUT ;
    USE SIGNAL ;
    PORT
      LAYER M4 ;
        RECT  0.054 19.2 0.138 19.224 ;
    END
  END x[68]
  PIN x[69]
    DIRECTION INPUT ;
    USE SIGNAL ;
    PORT
      LAYER M4 ;
        RECT  0.054 19.392 0.138 19.416 ;
    END
  END x[69]
  PIN x[6]
    DIRECTION INPUT ;
    USE SIGNAL ;
    PORT
      LAYER M4 ;
        RECT  0.054 6.624 0.138 6.648 ;
    END
  END x[6]
  PIN x[70]
    DIRECTION INPUT ;
    USE SIGNAL ;
    PORT
      LAYER M4 ;
        RECT  0.054 19.584 0.138 19.608 ;
    END
  END x[70]
  PIN x[71]
    DIRECTION INPUT ;
    USE SIGNAL ;
    PORT
      LAYER M4 ;
        RECT  0.054 19.824 0.138 19.848 ;
    END
  END x[71]
  PIN x[72]
    DIRECTION INPUT ;
    USE SIGNAL ;
    PORT
      LAYER M4 ;
        RECT  0.054 20.016 0.138 20.04 ;
    END
  END x[72]
  PIN x[73]
    DIRECTION INPUT ;
    USE SIGNAL ;
    PORT
      LAYER M4 ;
        RECT  0.054 20.208 0.138 20.232 ;
    END
  END x[73]
  PIN x[74]
    DIRECTION INPUT ;
    USE SIGNAL ;
    PORT
      LAYER M4 ;
        RECT  0.054 20.4 0.138 20.424 ;
    END
  END x[74]
  PIN x[75]
    DIRECTION INPUT ;
    USE SIGNAL ;
    PORT
      LAYER M4 ;
        RECT  0.054 20.592 0.138 20.616 ;
    END
  END x[75]
  PIN x[76]
    DIRECTION INPUT ;
    USE SIGNAL ;
    PORT
      LAYER M4 ;
        RECT  0.054 20.832 0.138 20.856 ;
    END
  END x[76]
  PIN x[77]
    DIRECTION INPUT ;
    USE SIGNAL ;
    PORT
      LAYER M4 ;
        RECT  0.054 21.024 0.138 21.048 ;
    END
  END x[77]
  PIN x[78]
    DIRECTION INPUT ;
    USE SIGNAL ;
    PORT
      LAYER M4 ;
        RECT  0.054 21.216 0.138 21.24 ;
    END
  END x[78]
  PIN x[79]
    DIRECTION INPUT ;
    USE SIGNAL ;
    PORT
      LAYER M4 ;
        RECT  0.054 21.408 0.138 21.432 ;
    END
  END x[79]
  PIN x[7]
    DIRECTION INPUT ;
    USE SIGNAL ;
    PORT
      LAYER M4 ;
        RECT  0.054 6.816 0.138 6.84 ;
    END
  END x[7]
  PIN x[80]
    DIRECTION INPUT ;
    USE SIGNAL ;
    PORT
      LAYER M4 ;
        RECT  0.054 21.648 0.138 21.672 ;
    END
  END x[80]
  PIN x[81]
    DIRECTION INPUT ;
    USE SIGNAL ;
    PORT
      LAYER M4 ;
        RECT  0.054 21.84 0.138 21.864 ;
    END
  END x[81]
  PIN x[82]
    DIRECTION INPUT ;
    USE SIGNAL ;
    PORT
      LAYER M4 ;
        RECT  0.054 22.032 0.138 22.056 ;
    END
  END x[82]
  PIN x[83]
    DIRECTION INPUT ;
    USE SIGNAL ;
    PORT
      LAYER M4 ;
        RECT  0.054 22.224 0.138 22.248 ;
    END
  END x[83]
  PIN x[84]
    DIRECTION INPUT ;
    USE SIGNAL ;
    PORT
      LAYER M4 ;
        RECT  0.054 22.464 0.138 22.488 ;
    END
  END x[84]
  PIN x[85]
    DIRECTION INPUT ;
    USE SIGNAL ;
    PORT
      LAYER M4 ;
        RECT  0.054 22.656 0.138 22.68 ;
    END
  END x[85]
  PIN x[86]
    DIRECTION INPUT ;
    USE SIGNAL ;
    PORT
      LAYER M4 ;
        RECT  0.054 22.848 0.138 22.872 ;
    END
  END x[86]
  PIN x[87]
    DIRECTION INPUT ;
    USE SIGNAL ;
    PORT
      LAYER M4 ;
        RECT  0.054 23.04 0.138 23.064 ;
    END
  END x[87]
  PIN x[88]
    DIRECTION INPUT ;
    USE SIGNAL ;
    PORT
      LAYER M4 ;
        RECT  0.054 23.232 0.138 23.256 ;
    END
  END x[88]
  PIN x[89]
    DIRECTION INPUT ;
    USE SIGNAL ;
    PORT
      LAYER M4 ;
        RECT  0.054 23.472 0.138 23.496 ;
    END
  END x[89]
  PIN x[8]
    DIRECTION INPUT ;
    USE SIGNAL ;
    PORT
      LAYER M4 ;
        RECT  0.054 7.008 0.138 7.032 ;
    END
  END x[8]
  PIN x[90]
    DIRECTION INPUT ;
    USE SIGNAL ;
    PORT
      LAYER M4 ;
        RECT  0.054 23.664 0.138 23.688 ;
    END
  END x[90]
  PIN x[91]
    DIRECTION INPUT ;
    USE SIGNAL ;
    PORT
      LAYER M4 ;
        RECT  0.054 23.856 0.138 23.88 ;
    END
  END x[91]
  PIN x[92]
    DIRECTION INPUT ;
    USE SIGNAL ;
    PORT
      LAYER M4 ;
        RECT  0.054 24.048 0.138 24.072 ;
    END
  END x[92]
  PIN x[93]
    DIRECTION INPUT ;
    USE SIGNAL ;
    PORT
      LAYER M4 ;
        RECT  0.054 24.288 0.138 24.312 ;
    END
  END x[93]
  PIN x[94]
    DIRECTION INPUT ;
    USE SIGNAL ;
    PORT
      LAYER M4 ;
        RECT  0.054 24.48 0.138 24.504 ;
    END
  END x[94]
  PIN x[95]
    DIRECTION INPUT ;
    USE SIGNAL ;
    PORT
      LAYER M4 ;
        RECT  0.054 24.672 0.138 24.696 ;
    END
  END x[95]
  PIN x[96]
    DIRECTION INPUT ;
    USE SIGNAL ;
    PORT
      LAYER M4 ;
        RECT  0.054 24.864 0.138 24.888 ;
    END
  END x[96]
  PIN x[97]
    DIRECTION INPUT ;
    USE SIGNAL ;
    PORT
      LAYER M4 ;
        RECT  0.054 25.056 0.138 25.08 ;
    END
  END x[97]
  PIN x[98]
    DIRECTION INPUT ;
    USE SIGNAL ;
    PORT
      LAYER M4 ;
        RECT  0.054 25.296 0.138 25.32 ;
    END
  END x[98]
  PIN x[99]
    DIRECTION INPUT ;
    USE SIGNAL ;
    PORT
      LAYER M4 ;
        RECT  0.054 25.488 0.138 25.512 ;
    END
  END x[99]
  PIN x[9]
    DIRECTION INPUT ;
    USE SIGNAL ;
    PORT
      LAYER M4 ;
        RECT  0.054 7.2 0.138 7.224 ;
    END
  END x[9]
  PIN VDD
    DIRECTION INOUT ;
    USE POWER ;
    PORT
      LAYER M5 ;
        RECT  10.692 2.151 10.812 62.649 ;
        RECT  7.992 2.151 8.112 62.649 ;
        RECT  5.292 2.151 5.412 62.649 ;
        RECT  2.592 2.151 2.712 62.649 ;
    END
  END VDD
  PIN VSS
    DIRECTION INOUT ;
    USE GROUND ;
    PORT
      LAYER M5 ;
        RECT  10.5 2.137 10.62 62.663 ;
        RECT  7.8 2.137 7.92 62.663 ;
        RECT  5.1 2.137 5.22 62.663 ;
        RECT  2.4 2.137 2.52 62.663 ;
    END
  END VSS
  # OT_OBS_CLOSED layer=M5 d_um=1.536 added=14
  OBS
    LAYER RVTN ;
     RECT  2.16 2.16 12.96 2.295 ;
     RECT  2.16 2.565 12.96 2.835 ;
     RECT  2.16 3.105 12.96 3.375 ;
     RECT  2.16 3.645 12.96 3.915 ;
     RECT  2.16 4.185 12.96 4.455 ;
     RECT  2.16 4.725 12.96 4.995 ;
     RECT  2.16 5.265 12.96 5.535 ;
     RECT  2.16 5.805 12.96 6.075 ;
     RECT  2.16 6.345 12.96 6.615 ;
     RECT  2.16 6.885 12.96 7.155 ;
     RECT  2.16 7.425 12.96 7.695 ;
     RECT  2.16 7.965 12.96 8.235 ;
     RECT  2.16 8.505 12.96 8.775 ;
     RECT  2.16 9.045 12.96 9.315 ;
     RECT  2.16 9.585 12.96 9.855 ;
     RECT  2.16 10.125 12.96 10.395 ;
     RECT  2.16 10.665 12.96 10.935 ;
     RECT  2.16 11.205 12.96 11.475 ;
     RECT  2.16 11.745 12.96 12.015 ;
     RECT  2.16 12.285 12.96 12.555 ;
     RECT  2.16 12.825 12.96 13.095 ;
     RECT  2.16 13.365 12.96 13.635 ;
     RECT  2.16 13.905 12.96 14.175 ;
     RECT  2.16 14.445 12.96 14.715 ;
     RECT  2.16 14.985 12.96 15.255 ;
     RECT  2.16 15.525 12.96 15.795 ;
     RECT  2.16 16.065 12.96 16.335 ;
     RECT  2.16 16.605 12.96 16.875 ;
     RECT  2.16 17.145 12.96 17.415 ;
     RECT  2.16 17.685 12.96 17.955 ;
     RECT  2.16 18.225 12.96 18.495 ;
     RECT  2.16 18.765 12.96 19.035 ;
     RECT  2.16 19.305 12.96 19.575 ;
     RECT  2.16 19.845 12.96 20.115 ;
     RECT  2.16 20.385 12.96 20.655 ;
     RECT  2.16 20.925 12.96 21.195 ;
     RECT  2.16 21.465 12.96 21.735 ;
     RECT  2.16 22.005 12.96 22.275 ;
     RECT  2.16 22.545 12.96 22.815 ;
     RECT  2.16 23.085 12.96 23.355 ;
     RECT  2.16 23.625 12.96 23.895 ;
     RECT  2.16 24.165 12.96 24.435 ;
     RECT  2.16 24.705 12.96 24.975 ;
     RECT  2.16 25.245 12.96 25.515 ;
     RECT  2.16 25.785 12.96 26.055 ;
     RECT  2.16 26.325 12.96 26.595 ;
     RECT  2.16 26.865 12.96 27.135 ;
     RECT  2.16 27.405 12.96 27.675 ;
     RECT  2.16 27.945 12.96 28.215 ;
     RECT  2.16 28.485 12.96 28.755 ;
     RECT  2.16 29.025 12.96 29.295 ;
     RECT  2.16 29.565 12.96 29.835 ;
     RECT  2.16 30.105 12.96 30.375 ;
     RECT  2.16 30.645 12.96 30.915 ;
     RECT  2.16 31.185 12.96 31.455 ;
     RECT  2.16 31.725 12.96 31.995 ;
     RECT  2.16 32.265 12.96 32.535 ;
     RECT  2.16 32.805 12.96 33.075 ;
     RECT  2.16 33.345 12.96 33.615 ;
     RECT  2.16 33.885 12.96 34.155 ;
     RECT  2.16 34.425 12.96 34.695 ;
     RECT  2.16 34.965 12.96 35.235 ;
     RECT  2.16 35.505 12.96 35.775 ;
     RECT  2.16 36.045 12.96 36.315 ;
     RECT  2.16 36.585 12.96 36.855 ;
     RECT  2.16 37.125 12.96 37.395 ;
     RECT  2.16 37.665 12.96 37.935 ;
     RECT  2.16 38.205 12.96 38.475 ;
     RECT  2.16 38.745 12.96 39.015 ;
     RECT  2.16 39.285 12.96 39.555 ;
     RECT  2.16 39.825 12.96 40.095 ;
     RECT  2.16 40.365 12.96 40.635 ;
     RECT  2.16 40.905 12.96 41.175 ;
     RECT  2.16 41.445 12.96 41.715 ;
     RECT  2.16 41.985 12.96 42.255 ;
     RECT  2.16 42.525 12.96 42.795 ;
     RECT  2.16 43.065 12.96 43.335 ;
     RECT  2.16 43.605 12.96 43.875 ;
     RECT  2.16 44.145 12.96 44.415 ;
     RECT  2.16 44.685 12.96 44.955 ;
     RECT  2.16 45.225 12.96 45.495 ;
     RECT  2.16 45.765 12.96 46.035 ;
     RECT  2.16 46.305 12.96 46.575 ;
     RECT  2.16 46.845 12.96 47.115 ;
     RECT  2.16 47.385 12.96 47.655 ;
     RECT  2.16 47.925 12.96 48.195 ;
     RECT  2.16 48.465 12.96 48.735 ;
     RECT  2.16 49.005 12.96 49.275 ;
     RECT  2.16 49.545 12.96 49.815 ;
     RECT  2.16 50.085 12.96 50.355 ;
     RECT  2.16 50.625 12.96 50.895 ;
     RECT  2.16 51.165 12.96 51.435 ;
     RECT  2.16 51.705 12.96 51.975 ;
     RECT  2.16 52.245 12.96 52.515 ;
     RECT  2.16 52.785 12.96 53.055 ;
     RECT  2.16 53.325 12.96 53.595 ;
     RECT  2.16 53.865 12.96 54.135 ;
     RECT  2.16 54.405 12.96 54.675 ;
     RECT  2.16 54.945 12.96 55.215 ;
     RECT  2.16 55.485 12.96 55.755 ;
     RECT  2.16 56.025 12.96 56.295 ;
     RECT  2.16 56.565 12.96 56.835 ;
     RECT  2.16 57.105 12.96 57.375 ;
     RECT  2.16 57.645 12.96 57.915 ;
     RECT  2.16 58.185 12.96 58.455 ;
     RECT  2.16 58.725 12.96 58.995 ;
     RECT  2.16 59.265 12.96 59.535 ;
     RECT  2.16 59.805 12.96 60.075 ;
     RECT  2.16 60.345 12.96 60.615 ;
     RECT  2.16 60.885 12.96 61.155 ;
     RECT  2.16 61.425 12.96 61.695 ;
     RECT  2.16 61.965 12.96 62.235 ;
     RECT  2.16 62.505 12.96 62.64 ;
    LAYER RVTP ;
     RECT  2.16 2.295 12.96 2.565 ;
     RECT  2.16 2.835 12.96 3.105 ;
     RECT  2.16 3.375 12.96 3.645 ;
     RECT  2.16 3.915 12.96 4.185 ;
     RECT  2.16 4.455 12.96 4.725 ;
     RECT  2.16 4.995 12.96 5.265 ;
     RECT  2.16 5.535 12.96 5.805 ;
     RECT  2.16 6.075 12.96 6.345 ;
     RECT  2.16 6.615 12.96 6.885 ;
     RECT  2.16 7.155 12.96 7.425 ;
     RECT  2.16 7.695 12.96 7.965 ;
     RECT  2.16 8.235 12.96 8.505 ;
     RECT  2.16 8.775 12.96 9.045 ;
     RECT  2.16 9.315 12.96 9.585 ;
     RECT  2.16 9.855 12.96 10.125 ;
     RECT  2.16 10.395 12.96 10.665 ;
     RECT  2.16 10.935 12.96 11.205 ;
     RECT  2.16 11.475 12.96 11.745 ;
     RECT  2.16 12.015 12.96 12.285 ;
     RECT  2.16 12.555 12.96 12.825 ;
     RECT  2.16 13.095 12.96 13.365 ;
     RECT  2.16 13.635 12.96 13.905 ;
     RECT  2.16 14.175 12.96 14.445 ;
     RECT  2.16 14.715 12.96 14.985 ;
     RECT  2.16 15.255 12.96 15.525 ;
     RECT  2.16 15.795 12.96 16.065 ;
     RECT  2.16 16.335 12.96 16.605 ;
     RECT  2.16 16.875 12.96 17.145 ;
     RECT  2.16 17.415 12.96 17.685 ;
     RECT  2.16 17.955 12.96 18.225 ;
     RECT  2.16 18.495 12.96 18.765 ;
     RECT  2.16 19.035 12.96 19.305 ;
     RECT  2.16 19.575 12.96 19.845 ;
     RECT  2.16 20.115 12.96 20.385 ;
     RECT  2.16 20.655 12.96 20.925 ;
     RECT  2.16 21.195 12.96 21.465 ;
     RECT  2.16 21.735 12.96 22.005 ;
     RECT  2.16 22.275 12.96 22.545 ;
     RECT  2.16 22.815 12.96 23.085 ;
     RECT  2.16 23.355 12.96 23.625 ;
     RECT  2.16 23.895 12.96 24.165 ;
     RECT  2.16 24.435 12.96 24.705 ;
     RECT  2.16 24.975 12.96 25.245 ;
     RECT  2.16 25.515 12.96 25.785 ;
     RECT  2.16 26.055 12.96 26.325 ;
     RECT  2.16 26.595 12.96 26.865 ;
     RECT  2.16 27.135 12.96 27.405 ;
     RECT  2.16 27.675 12.96 27.945 ;
     RECT  2.16 28.215 12.96 28.485 ;
     RECT  2.16 28.755 12.96 29.025 ;
     RECT  2.16 29.295 12.96 29.565 ;
     RECT  2.16 29.835 12.96 30.105 ;
     RECT  2.16 30.375 12.96 30.645 ;
     RECT  2.16 30.915 12.96 31.185 ;
     RECT  2.16 31.455 12.96 31.725 ;
     RECT  2.16 31.995 12.96 32.265 ;
     RECT  2.16 32.535 12.96 32.805 ;
     RECT  2.16 33.075 12.96 33.345 ;
     RECT  2.16 33.615 12.96 33.885 ;
     RECT  2.16 34.155 12.96 34.425 ;
     RECT  2.16 34.695 12.96 34.965 ;
     RECT  2.16 35.235 12.96 35.505 ;
     RECT  2.16 35.775 12.96 36.045 ;
     RECT  2.16 36.315 12.96 36.585 ;
     RECT  2.16 36.855 12.96 37.125 ;
     RECT  2.16 37.395 12.96 37.665 ;
     RECT  2.16 37.935 12.96 38.205 ;
     RECT  2.16 38.475 12.96 38.745 ;
     RECT  2.16 39.015 12.96 39.285 ;
     RECT  2.16 39.555 12.96 39.825 ;
     RECT  2.16 40.095 12.96 40.365 ;
     RECT  2.16 40.635 12.96 40.905 ;
     RECT  2.16 41.175 12.96 41.445 ;
     RECT  2.16 41.715 12.96 41.985 ;
     RECT  2.16 42.255 12.96 42.525 ;
     RECT  2.16 42.795 12.96 43.065 ;
     RECT  2.16 43.335 12.96 43.605 ;
     RECT  2.16 43.875 12.96 44.145 ;
     RECT  2.16 44.415 12.96 44.685 ;
     RECT  2.16 44.955 12.96 45.225 ;
     RECT  2.16 45.495 12.96 45.765 ;
     RECT  2.16 46.035 12.96 46.305 ;
     RECT  2.16 46.575 12.96 46.845 ;
     RECT  2.16 47.115 12.96 47.385 ;
     RECT  2.16 47.655 12.96 47.925 ;
     RECT  2.16 48.195 12.96 48.465 ;
     RECT  2.16 48.735 12.96 49.005 ;
     RECT  2.16 49.275 12.96 49.545 ;
     RECT  2.16 49.815 12.96 50.085 ;
     RECT  2.16 50.355 12.96 50.625 ;
     RECT  2.16 50.895 12.96 51.165 ;
     RECT  2.16 51.435 12.96 51.705 ;
     RECT  2.16 51.975 12.96 52.245 ;
     RECT  2.16 52.515 12.96 52.785 ;
     RECT  2.16 53.055 12.96 53.325 ;
     RECT  2.16 53.595 12.96 53.865 ;
     RECT  2.16 54.135 12.96 54.405 ;
     RECT  2.16 54.675 12.96 54.945 ;
     RECT  2.16 55.215 12.96 55.485 ;
     RECT  2.16 55.755 12.96 56.025 ;
     RECT  2.16 56.295 12.96 56.565 ;
     RECT  2.16 56.835 12.96 57.105 ;
     RECT  2.16 57.375 12.96 57.645 ;
     RECT  2.16 57.915 12.96 58.185 ;
     RECT  2.16 58.455 12.96 58.725 ;
     RECT  2.16 58.995 12.96 59.265 ;
     RECT  2.16 59.535 12.96 59.805 ;
     RECT  2.16 60.075 12.96 60.345 ;
     RECT  2.16 60.615 12.96 60.885 ;
     RECT  2.16 61.155 12.96 61.425 ;
     RECT  2.16 61.695 12.96 61.965 ;
     RECT  2.16 62.235 12.96 62.505 ;
    LAYER M1 ;
     RECT  2.16 2.151 12.96 62.649 ;
    LAYER M2 ;
     RECT  0.139 29.34 0.239 29.358 ;
     RECT  0.535 22.212 2.16 22.23 ;
     RECT  0.139 55.8 2.16 55.818 ;
     RECT  2.16 2.151 12.96 62.649 ;
     RECT  12.96 8.208 13.091 39.312 ;
     RECT  12.96 57.546 13.127 59.22 ;
     RECT  13.091 8.208 13.595 30.834 ;
     RECT  13.091 33.858 13.595 35.226 ;
     RECT  13.595 8.208 13.631 10.314 ;
     RECT  12.96 4.698 13.667 7.416 ;
     RECT  13.631 8.208 13.667 10.116 ;
     RECT  13.595 11.286 13.667 30.834 ;
     RECT  13.091 31.698 13.667 32.832 ;
     RECT  13.595 33.858 13.667 35.154 ;
     RECT  13.091 36.018 13.667 39.312 ;
     RECT  12.96 47.826 13.667 50.814 ;
     RECT  12.96 51.786 13.667 53.01 ;
     RECT  13.667 4.698 13.703 6.84 ;
     RECT  13.667 28.566 13.703 30.744 ;
     RECT  13.667 38.448 13.703 39.114 ;
     RECT  12.96 54.576 13.703 56.754 ;
     RECT  13.127 57.546 13.703 57.564 ;
     RECT  13.667 34.128 13.739 35.154 ;
     RECT  13.739 34.164 13.811 35.154 ;
     RECT  13.667 9.828 13.955 10.116 ;
     RECT  13.667 31.698 14.027 32.796 ;
     RECT  13.703 28.566 14.099 30.366 ;
     RECT  13.667 19.548 14.207 23.454 ;
     RECT  12.96 43.038 14.207 47.034 ;
     RECT  13.667 48.096 14.207 50.148 ;
     RECT  13.703 4.698 14.243 4.824 ;
     RECT  13.703 6.822 14.243 6.84 ;
     RECT  13.667 14.256 14.243 18.324 ;
     RECT  14.207 22.446 14.243 23.454 ;
     RECT  14.099 30.006 14.243 30.366 ;
     RECT  13.667 36.288 14.243 37.692 ;
     RECT  12.96 40.068 14.243 42.21 ;
     RECT  14.207 45.936 14.243 45.954 ;
     RECT  14.207 46.746 14.243 46.764 ;
     RECT  14.207 48.366 14.243 50.148 ;
     RECT  13.667 51.786 14.243 52.812 ;
     RECT  12.96 53.766 14.243 53.784 ;
     RECT  13.703 54.576 14.243 55.278 ;
     RECT  13.703 56.34 14.243 56.754 ;
     RECT  13.127 58.536 14.243 59.22 ;
     RECT  13.703 5.616 14.279 6.066 ;
     RECT  13.955 9.828 14.279 9.882 ;
     RECT  13.667 11.286 14.279 13.194 ;
     RECT  14.243 14.256 14.279 16.668 ;
     RECT  14.243 17.496 14.279 18.324 ;
     RECT  14.207 19.548 14.279 21.492 ;
     RECT  14.243 23.058 14.279 23.346 ;
     RECT  13.667 24.21 14.279 26.694 ;
     RECT  14.027 32.274 14.279 32.796 ;
     RECT  13.811 34.434 14.279 35.154 ;
     RECT  14.243 36.288 14.279 36.774 ;
     RECT  14.243 40.068 14.279 41.976 ;
     RECT  14.243 48.672 14.279 50.148 ;
     RECT  14.243 52.794 14.279 52.812 ;
     RECT  14.243 58.536 14.279 58.554 ;
     RECT  14.279 17.586 14.315 18.324 ;
     RECT  14.279 20.358 14.315 21.186 ;
     RECT  14.279 25.686 14.315 26.352 ;
     RECT  14.279 40.644 14.315 41.202 ;
     RECT  14.279 9.828 14.351 9.846 ;
     RECT  14.207 43.038 14.351 44.784 ;
     RECT  14.279 14.256 14.819 15.21 ;
     RECT  14.351 43.038 14.855 44.064 ;
     RECT  14.819 14.256 14.891 15.174 ;
     RECT  14.891 14.256 14.927 14.976 ;
     RECT  14.279 23.058 14.927 23.112 ;
     RECT  14.279 32.436 14.927 32.796 ;
     RECT  14.855 43.038 14.927 43.938 ;
     RECT  14.243 51.786 14.927 51.966 ;
     RECT  14.243 54.576 14.927 55.044 ;
     RECT  14.243 4.806 14.963 4.824 ;
     RECT  14.279 5.616 14.963 5.634 ;
     RECT  14.279 11.286 14.963 12.312 ;
     RECT  14.279 13.176 14.963 13.194 ;
     RECT  14.927 14.256 14.963 14.274 ;
     RECT  14.279 16.506 14.963 16.524 ;
     RECT  14.315 18.306 14.963 18.324 ;
     RECT  14.279 19.548 14.963 19.566 ;
     RECT  14.315 20.826 14.963 20.844 ;
     RECT  14.927 23.094 14.963 23.112 ;
     RECT  14.279 24.21 14.963 24.534 ;
     RECT  14.315 25.686 14.963 26.28 ;
     RECT  13.667 27.684 14.963 27.702 ;
     RECT  14.099 28.566 14.963 29.124 ;
     RECT  14.927 32.778 14.963 32.796 ;
     RECT  14.279 35.136 14.963 35.154 ;
     RECT  14.279 36.756 14.963 36.774 ;
     RECT  14.243 37.674 14.963 37.692 ;
     RECT  13.703 38.448 14.963 38.808 ;
     RECT  14.315 41.184 14.963 41.202 ;
     RECT  14.279 41.958 14.963 41.976 ;
     RECT  14.927 43.308 14.963 43.326 ;
     RECT  14.279 48.672 14.963 48.762 ;
     RECT  14.279 50.13 14.963 50.148 ;
     RECT  14.927 51.786 14.963 51.804 ;
     RECT  14.927 54.72 14.963 55.044 ;
     RECT  14.243 30.348 14.999 30.366 ;
     RECT  14.963 24.21 15.071 24.228 ;
     RECT  14.963 54.72 15.071 54.738 ;
    LAYER M3 ;
     RECT  9.684 0.571 9.702 2.191 ;
     RECT  8.82 2.191 9.702 2.255 ;
     RECT  8.82 2.255 9.486 2.291 ;
     RECT  9.072 2.291 9.486 2.399 ;
     RECT  2.415 2.143 2.505 2.413 ;
     RECT  5.115 2.143 5.205 2.413 ;
     RECT  7.815 2.143 7.905 2.413 ;
     RECT  10.515 2.143 10.605 2.413 ;
     RECT  9.072 2.399 9.306 2.489 ;
     RECT  9.072 2.489 9.162 2.525 ;
     RECT  12.564 3.685 12.582 3.721 ;
     RECT  12.564 3.721 12.906 4.765 ;
     RECT  14.22 4.693 14.238 4.801 ;
     RECT  12.06 4.765 12.906 5.035 ;
     RECT  12.06 5.035 13.086 5.071 ;
     RECT  2.415 2.413 2.697 5.197 ;
     RECT  5.115 2.413 5.397 5.197 ;
     RECT  4.536 5.197 5.397 5.233 ;
     RECT  10.515 2.413 10.797 5.305 ;
     RECT  2.415 5.197 3.294 5.341 ;
     RECT  4.212 5.233 5.397 5.341 ;
     RECT  12.06 5.071 13.122 5.341 ;
     RECT  2.415 5.341 5.397 5.419 ;
     RECT  11.844 5.341 13.158 5.431 ;
     RECT  14.22 4.801 14.958 5.431 ;
     RECT  2.304 5.419 5.397 5.575 ;
     RECT  6.912 5.539 6.93 5.575 ;
     RECT  7.815 2.413 8.097 5.575 ;
     RECT  10.515 5.305 10.89 5.575 ;
     RECT  11.844 5.431 14.958 5.575 ;
     RECT  2.304 5.575 8.097 5.737 ;
     RECT  9.072 2.525 9.09 5.737 ;
     RECT  10.515 5.575 14.958 5.737 ;
     RECT  2.304 5.737 9.45 5.773 ;
     RECT  10.26 5.737 14.958 5.773 ;
     RECT  2.304 5.773 14.958 6.035 ;
     RECT  2.415 6.035 14.958 6.221 ;
     RECT  2.415 6.221 14.274 6.653 ;
     RECT  2.415 6.653 14.238 6.845 ;
     RECT  2.415 6.845 13.698 7.003 ;
     RECT  2.304 7.003 13.698 7.037 ;
     RECT  2.304 7.037 13.662 7.421 ;
     RECT  2.304 7.421 13.122 7.469 ;
     RECT  2.304 7.469 12.906 7.661 ;
     RECT  2.304 7.661 12.87 8.045 ;
     RECT  2.304 8.045 12.69 8.827 ;
     RECT  13.644 8.203 13.662 8.827 ;
     RECT  2.304 8.827 13.662 9.451 ;
     RECT  2.304 9.451 14.274 9.643 ;
     RECT  2.304 9.643 14.346 9.851 ;
     RECT  2.304 9.851 14.274 9.887 ;
     RECT  2.304 9.887 13.95 10.699 ;
     RECT  2.304 10.699 14.238 11.272 ;
     RECT  2.304 11.272 14.958 11.399 ;
     RECT  2.304 11.399 13.95 12.793 ;
     RECT  14.94 11.399 14.958 12.793 ;
     RECT  2.304 12.793 14.958 12.941 ;
     RECT  14.94 12.941 14.958 13.199 ;
     RECT  2.304 12.941 13.95 13.963 ;
     RECT  2.304 13.963 14.274 14.155 ;
     RECT  2.304 14.155 14.958 14.279 ;
     RECT  2.304 14.279 14.922 14.981 ;
     RECT  2.304 14.981 14.886 15.179 ;
     RECT  2.304 15.179 14.814 15.215 ;
     RECT  2.304 15.215 14.274 15.251 ;
     RECT  2.34 15.251 14.274 16.171 ;
     RECT  0.144 16.123 0.162 16.301 ;
     RECT  2.34 16.171 14.958 16.363 ;
     RECT  2.304 16.363 14.958 16.529 ;
     RECT  2.304 16.529 14.274 17.581 ;
     RECT  2.304 17.581 14.31 17.752 ;
     RECT  2.268 17.752 14.31 18.235 ;
     RECT  2.268 18.235 14.958 18.329 ;
     RECT  2.268 18.329 14.274 18.527 ;
     RECT  2.304 18.527 14.274 19.051 ;
     RECT  0.144 19.195 0.162 19.325 ;
     RECT  2.304 19.051 14.958 19.571 ;
     RECT  2.304 19.571 14.31 20.443 ;
     RECT  2.304 20.443 14.958 20.849 ;
     RECT  2.304 20.849 14.31 21.191 ;
     RECT  2.304 21.191 14.274 21.497 ;
     RECT  0.54 22.207 0.558 22.253 ;
     RECT  2.304 21.497 14.238 22.507 ;
     RECT  2.304 22.507 14.958 22.651 ;
     RECT  2.268 22.651 14.958 23.117 ;
     RECT  2.268 23.117 14.274 23.315 ;
     RECT  2.304 23.315 14.274 24.139 ;
     RECT  2.304 24.139 14.31 24.331 ;
     RECT  15.048 24.205 15.066 24.331 ;
     RECT  2.304 24.331 15.066 24.539 ;
     RECT  2.304 24.539 14.31 25.579 ;
     RECT  15.048 24.539 15.066 25.579 ;
     RECT  2.304 25.579 15.066 26.357 ;
     RECT  2.304 26.357 14.274 26.699 ;
     RECT  15.012 26.357 15.066 27.595 ;
     RECT  2.304 26.699 14.058 28.123 ;
     RECT  2.268 28.123 14.058 28.445 ;
     RECT  2.304 28.445 14.058 29.035 ;
     RECT  14.94 27.595 15.066 29.035 ;
     RECT  2.304 29.035 15.066 29.129 ;
     RECT  0.144 29.323 0.162 29.335 ;
     RECT  0.144 29.335 0.234 29.363 ;
     RECT  0.216 29.363 0.234 29.549 ;
     RECT  2.304 29.129 14.238 30.029 ;
     RECT  15.012 29.129 15.066 30.343 ;
     RECT  0.144 30.763 0.162 30.893 ;
     RECT  2.304 30.029 14.094 31.415 ;
     RECT  2.34 31.415 14.094 31.483 ;
     RECT  14.976 30.343 15.066 31.483 ;
     RECT  2.34 31.483 15.066 32.297 ;
     RECT  2.34 32.297 14.094 32.395 ;
     RECT  14.904 32.297 15.066 32.717 ;
     RECT  14.94 32.717 15.066 32.801 ;
     RECT  2.304 32.395 14.094 34.429 ;
     RECT  14.976 32.801 15.066 34.429 ;
     RECT  0.144 36.331 0.162 36.461 ;
     RECT  2.304 34.429 15.066 37.157 ;
     RECT  2.304 37.157 14.094 38.479 ;
     RECT  2.304 38.479 14.13 39.019 ;
     RECT  14.94 37.157 15.066 39.019 ;
     RECT  2.304 39.019 15.066 52.493 ;
     RECT  12.924 52.493 15.066 53.671 ;
     RECT  12.6 53.671 15.066 53.693 ;
     RECT  12.6 53.693 12.942 53.933 ;
     RECT  14.004 53.693 15.066 54.187 ;
     RECT  2.304 52.493 11.79 54.301 ;
     RECT  12.6 53.933 12.762 54.301 ;
     RECT  14.004 54.187 15.102 54.317 ;
     RECT  2.304 54.301 12.762 54.671 ;
     RECT  14.004 54.317 15.066 54.743 ;
     RECT  2.304 54.671 12.51 54.905 ;
     RECT  2.304 54.905 12.366 54.985 ;
     RECT  2.268 54.985 12.366 55.133 ;
     RECT  14.004 54.743 14.994 55.831 ;
     RECT  0.144 55.795 0.162 55.949 ;
     RECT  13.68 55.831 14.994 55.949 ;
     RECT  13.104 56.101 13.122 56.141 ;
     RECT  2.304 55.133 12.366 56.327 ;
     RECT  2.304 56.327 8.097 56.489 ;
     RECT  8.928 56.327 12.366 56.561 ;
     RECT  14.004 55.949 14.994 56.759 ;
     RECT  12.636 56.641 12.654 56.795 ;
     RECT  14.796 56.759 14.994 57.067 ;
     RECT  14.796 57.067 15.102 57.197 ;
     RECT  4.536 56.489 8.097 57.379 ;
     RECT  2.304 56.489 3.546 57.451 ;
     RECT  4.284 57.379 8.097 57.451 ;
     RECT  8.928 56.561 11.79 57.541 ;
     RECT  14.004 56.759 14.022 57.541 ;
     RECT  14.796 57.197 14.814 57.581 ;
     RECT  8.928 57.541 11.97 57.641 ;
     RECT  13.68 57.541 14.022 57.773 ;
     RECT  2.304 57.451 8.097 57.931 ;
     RECT  13.68 57.773 13.698 57.979 ;
     RECT  8.928 57.641 11.79 57.983 ;
     RECT  13.068 57.979 13.698 58.019 ;
     RECT  2.304 57.931 8.154 58.109 ;
     RECT  8.928 57.983 9.45 58.109 ;
     RECT  8.928 58.109 9.414 58.117 ;
     RECT  13.104 58.019 13.698 58.205 ;
     RECT  8.892 58.117 9.414 58.415 ;
     RECT  10.476 57.983 11.79 58.801 ;
     RECT  13.104 58.205 13.122 58.801 ;
     RECT  10.476 58.801 13.122 58.829 ;
     RECT  14.256 58.531 14.274 58.829 ;
     RECT  8.928 58.415 9.414 58.919 ;
     RECT  10.515 58.829 13.122 58.955 ;
     RECT  8.928 58.919 8.982 59.027 ;
     RECT  7.272 58.109 8.154 59.099 ;
     RECT  2.304 58.109 6.534 59.189 ;
     RECT  8.964 59.027 8.982 59.189 ;
     RECT  11.736 58.955 12.186 59.225 ;
     RECT  14.22 58.987 14.238 59.225 ;
     RECT  2.304 59.189 4.23 59.261 ;
     RECT  13.104 58.955 13.122 59.405 ;
     RECT  5.004 59.189 6.534 59.459 ;
     RECT  2.304 59.261 4.05 59.495 ;
     RECT  5.004 59.459 5.706 59.495 ;
     RECT  6.444 59.459 6.534 59.531 ;
     RECT  7.272 59.099 8.097 59.575 ;
     RECT  5.004 59.495 5.397 59.729 ;
     RECT  6.624 59.575 8.097 59.729 ;
     RECT  2.34 59.495 3.438 59.765 ;
     RECT  5.112 59.729 5.397 59.765 ;
     RECT  2.415 59.765 3.438 59.999 ;
     RECT  2.415 59.999 3.15 60.035 ;
     RECT  2.415 60.035 2.697 62.387 ;
     RECT  5.115 59.765 5.397 62.387 ;
     RECT  7.815 59.729 8.097 62.387 ;
     RECT  10.515 58.955 10.797 62.387 ;
     RECT  2.415 62.387 2.505 62.657 ;
     RECT  5.115 62.387 5.205 62.657 ;
     RECT  7.815 62.387 7.905 62.657 ;
     RECT  10.515 62.387 10.605 62.657 ;
    LAYER M4 ;
     RECT  0.085 1.392 0.108 1.416 ;
     RECT  0.085 29.424 0.108 29.448 ;
     RECT  0.108 5.424 2.408 59.4 ;
     RECT  2.408 2.148 2.512 62.652 ;
     RECT  2.512 2.418 2.704 62.382 ;
     RECT  2.704 55.536 2.729 57.432 ;
     RECT  2.704 17.616 2.765 17.976 ;
     RECT  2.704 47.424 2.801 47.448 ;
     RECT  2.704 48.432 2.801 49.272 ;
     RECT  2.704 50.64 2.801 50.904 ;
     RECT  2.729 55.872 2.801 57.432 ;
     RECT  2.704 44.352 2.837 45 ;
     RECT  2.704 24.288 2.867 25.656 ;
     RECT  2.801 48.432 2.873 48.456 ;
     RECT  2.801 50.64 3.017 50.664 ;
     RECT  2.704 34.848 3.061 35.352 ;
     RECT  2.837 44.448 3.061 45 ;
     RECT  3.061 44.976 3.089 45 ;
     RECT  2.704 38.688 3.125 39.336 ;
     RECT  2.704 5.568 3.197 13.08 ;
     RECT  3.061 35.328 3.277 35.352 ;
     RECT  2.801 55.872 3.413 55.896 ;
     RECT  3.197 5.616 3.443 13.08 ;
     RECT  2.704 36.336 3.683 37.176 ;
     RECT  2.704 22.224 3.733 23.256 ;
     RECT  2.867 24.288 3.733 25.512 ;
     RECT  2.765 17.616 3.769 17.928 ;
     RECT  2.704 27.168 3.781 27.96 ;
     RECT  2.704 19.056 3.805 21 ;
     RECT  3.733 22.224 3.805 25.512 ;
     RECT  3.769 17.568 3.829 17.928 ;
     RECT  3.443 6.048 3.841 13.08 ;
     RECT  2.704 14.208 3.841 16.536 ;
     RECT  3.797 48.48 3.881 48.504 ;
     RECT  3.829 17.52 3.913 17.928 ;
     RECT  3.805 19.056 3.913 25.512 ;
     RECT  3.781 27.12 3.913 27.96 ;
     RECT  3.913 17.52 3.985 27.96 ;
     RECT  2.704 42.768 4.057 43.08 ;
     RECT  3.841 6.048 4.093 16.536 ;
     RECT  3.985 17.52 4.093 28.248 ;
     RECT  4.093 6.048 4.237 28.248 ;
     RECT  2.704 29.28 4.237 32.52 ;
     RECT  3.683 37.104 4.741 37.176 ;
     RECT  3.125 38.688 4.789 38.712 ;
     RECT  2.801 57.408 4.849 57.432 ;
     RECT  2.704 58.512 4.849 58.536 ;
     RECT  4.237 6.048 4.981 32.52 ;
     RECT  4.921 33.6 4.981 33.624 ;
     RECT  4.057 42.672 4.981 43.08 ;
     RECT  4.981 5.664 5.108 33.624 ;
     RECT  3.829 35.808 5.108 35.832 ;
     RECT  4.741 37.056 5.108 37.176 ;
     RECT  4.789 38.208 5.108 38.712 ;
     RECT  4.981 41.424 5.108 43.08 ;
     RECT  4.085 44.448 5.108 44.472 ;
     RECT  4.849 57.408 5.108 58.536 ;
     RECT  5.108 2.148 5.212 62.652 ;
     RECT  5.212 2.418 5.404 62.382 ;
     RECT  5.404 46.224 5.555 46.728 ;
     RECT  5.404 57.408 5.555 58.152 ;
     RECT  5.404 39.888 6.257 39.912 ;
     RECT  5.404 48.48 6.301 48.504 ;
     RECT  6.428 38.832 6.461 38.856 ;
     RECT  5.404 43.008 6.469 43.08 ;
     RECT  5.555 58.128 6.473 58.152 ;
     RECT  6.469 42.768 6.517 43.08 ;
     RECT  6.461 38.832 6.545 39 ;
     RECT  5.555 46.224 6.563 46.248 ;
     RECT  6.517 42.144 6.565 43.08 ;
     RECT  5.404 5.904 6.613 33.624 ;
     RECT  5.404 34.8 6.613 34.824 ;
     RECT  6.613 5.904 6.709 34.824 ;
     RECT  5.404 35.808 6.709 37.32 ;
     RECT  6.565 42.048 6.829 43.08 ;
     RECT  6.709 5.904 6.865 37.32 ;
     RECT  6.505 47.568 7.009 47.928 ;
     RECT  6.829 50.928 7.093 50.952 ;
     RECT  6.829 42 7.189 43.08 ;
     RECT  6.541 44.304 7.189 44.328 ;
     RECT  6.865 5.904 7.237 37.416 ;
     RECT  7.081 38.784 7.237 38.808 ;
     RECT  6.973 56.256 7.429 56.28 ;
     RECT  7.189 41.952 7.657 44.328 ;
     RECT  7.237 5.904 7.808 38.808 ;
     RECT  7.657 41.376 7.808 44.328 ;
     RECT  7.009 46.656 7.808 47.928 ;
     RECT  7.093 50.928 7.808 51.72 ;
     RECT  7.429 55.536 7.808 56.28 ;
     RECT  6.901 57.36 7.808 57.384 ;
     RECT  7.808 2.148 7.912 62.652 ;
     RECT  7.912 2.418 8.104 62.382 ;
     RECT  8.104 30.096 8.201 36.312 ;
     RECT  8.104 37.392 8.284 44.472 ;
     RECT  8.104 53.232 8.291 54.168 ;
     RECT  8.104 55.536 8.291 56.28 ;
     RECT  8.104 57.36 8.291 57.96 ;
     RECT  8.284 37.392 8.309 40.344 ;
     RECT  8.201 30.096 8.381 31.896 ;
     RECT  8.201 33.6 8.597 36.312 ;
     RECT  8.597 34.368 8.849 36.312 ;
     RECT  8.284 41.376 8.849 44.472 ;
     RECT  8.104 11.424 8.867 28.728 ;
     RECT  8.309 37.44 8.921 40.344 ;
     RECT  8.867 11.712 9.065 28.728 ;
     RECT  9.065 17.232 9.107 28.728 ;
     RECT  8.921 37.44 9.107 39.384 ;
     RECT  9.065 11.712 9.137 16.104 ;
     RECT  8.104 50.16 9.137 51.72 ;
     RECT  9.107 37.44 9.148 37.464 ;
     RECT  9.107 25.056 9.173 28.728 ;
     RECT  8.104 6.048 9.245 10.344 ;
     RECT  8.104 47.664 9.397 47.928 ;
     RECT  8.849 44.448 9.457 44.472 ;
     RECT  9.397 47.664 9.457 48.744 ;
     RECT  9.107 17.232 9.497 23.976 ;
     RECT  9.457 44.448 9.529 44.952 ;
     RECT  9.457 46.752 9.541 48.744 ;
     RECT  9.245 6.048 9.673 6.072 ;
     RECT  8.849 35.808 9.709 36.312 ;
     RECT  9.673 0.576 9.757 0.6 ;
     RECT  9.107 38.64 9.889 39.384 ;
     RECT  8.849 41.376 9.889 43.32 ;
     RECT  9.889 38.64 9.997 39.624 ;
     RECT  9.889 40.656 9.997 43.32 ;
     RECT  9.173 25.056 10.249 28.488 ;
     RECT  9.709 35.808 10.501 36.648 ;
     RECT  9.673 5.904 10.508 6.072 ;
     RECT  9.245 7.2 10.508 10.344 ;
     RECT  9.137 11.904 10.508 16.104 ;
     RECT  9.497 17.232 10.508 21 ;
     RECT  9.497 22.368 10.508 23.976 ;
     RECT  10.249 25.056 10.508 28.824 ;
     RECT  8.381 30.096 10.508 31.608 ;
     RECT  8.849 34.368 10.508 34.776 ;
     RECT  10.501 35.808 10.508 37.08 ;
     RECT  9.997 38.64 10.508 43.32 ;
     RECT  9.529 44.448 10.508 45 ;
     RECT  9.541 46.848 10.508 48.744 ;
     RECT  9.137 50.448 10.508 51.72 ;
     RECT  8.291 54.144 10.508 54.168 ;
     RECT  8.291 55.536 10.508 55.56 ;
     RECT  8.291 57.36 10.508 57.384 ;
     RECT  10.508 2.148 10.612 62.652 ;
     RECT  10.612 2.418 10.804 62.382 ;
     RECT  10.804 10.176 10.865 10.344 ;
     RECT  10.804 17.52 10.901 20.088 ;
     RECT  10.901 17.52 10.931 19.896 ;
     RECT  10.804 52.464 10.931 52.488 ;
     RECT  10.931 17.52 10.973 19.656 ;
     RECT  10.865 10.176 11.009 10.2 ;
     RECT  10.804 15.168 11.009 16.536 ;
     RECT  10.973 17.52 11.081 18.504 ;
     RECT  10.804 28.272 11.153 32.376 ;
     RECT  10.804 35.232 11.189 37.416 ;
     RECT  10.804 39.6 11.261 41.88 ;
     RECT  11.009 16.08 11.297 16.536 ;
     RECT  11.189 36.624 11.333 37.416 ;
     RECT  10.804 23.28 11.405 23.976 ;
     RECT  10.804 38.4 11.729 38.472 ;
     RECT  10.804 33.504 11.797 34.104 ;
     RECT  11.189 35.232 11.797 35.256 ;
     RECT  11.405 23.28 11.801 23.736 ;
     RECT  10.804 50.928 12.085 50.952 ;
     RECT  11.797 33.504 12.089 35.256 ;
     RECT  10.804 11.376 12.121 11.4 ;
     RECT  10.804 13.344 12.157 13.368 ;
     RECT  11.153 28.848 12.193 32.376 ;
     RECT  11.261 40.8 12.265 41.88 ;
     RECT  12.089 33.504 12.269 34.872 ;
     RECT  11.297 16.368 12.301 16.536 ;
     RECT  11.081 17.52 12.301 18.024 ;
     RECT  12.193 28.416 12.305 32.376 ;
     RECT  10.804 26.256 12.337 26.808 ;
     RECT  10.973 19.632 12.341 19.656 ;
     RECT  12.265 40.8 12.341 42.504 ;
     RECT  12.121 11.088 12.373 11.4 ;
     RECT  11.729 38.4 12.377 38.424 ;
     RECT  10.804 43.92 12.449 44.088 ;
     RECT  12.269 34.848 12.485 34.872 ;
     RECT  12.341 41.664 12.521 42.504 ;
     RECT  12.305 29.76 12.557 32.376 ;
     RECT  12.373 10.464 12.697 11.4 ;
     RECT  12.373 8.448 12.805 8.472 ;
     RECT  12.337 26.256 12.805 26.856 ;
     RECT  12.305 28.416 12.805 28.632 ;
     RECT  10.804 47.568 12.841 48.024 ;
     RECT  10.804 49.392 12.841 49.416 ;
     RECT  12.805 7.824 12.877 8.472 ;
     RECT  12.085 50.832 12.877 50.952 ;
     RECT  10.804 54.096 12.913 54.12 ;
     RECT  12.877 50.832 12.949 51.48 ;
     RECT  12.877 7.632 13.057 8.472 ;
     RECT  12.157 13.344 13.057 13.56 ;
     RECT  12.013 20.88 13.057 20.904 ;
     RECT  10.804 21.888 13.057 21.912 ;
     RECT  12.805 25.776 13.057 28.632 ;
     RECT  12.557 30.24 13.057 32.376 ;
     RECT  12.269 33.504 13.057 33.528 ;
     RECT  13.021 36.144 13.057 36.168 ;
     RECT  11.333 37.392 13.057 37.416 ;
     RECT  11.261 39.6 13.057 39.624 ;
     RECT  10.804 57.36 13.057 57.384 ;
     RECT  10.804 58.56 13.057 58.584 ;
     RECT  13.057 7.632 13.093 8.856 ;
     RECT  12.697 10.272 13.093 11.4 ;
     RECT  13.057 12.72 13.093 13.56 ;
     RECT  12.841 47.568 13.093 49.416 ;
     RECT  12.949 50.64 13.093 51.48 ;
     RECT  10.804 55.536 13.093 55.56 ;
     RECT  13.057 57.36 13.093 58.584 ;
     RECT  13.057 6 13.129 6.024 ;
     RECT  13.057 35.328 13.129 37.416 ;
     RECT  12.301 45.936 13.345 45.96 ;
     RECT  13.057 24.768 13.417 28.632 ;
     RECT  13.345 45.744 13.453 45.96 ;
     RECT  12.913 53.904 13.489 54.12 ;
     RECT  13.417 24.768 13.525 29.256 ;
     RECT  13.057 30.24 13.525 33.528 ;
     RECT  11.801 23.712 13.561 23.736 ;
     RECT  13.525 24.768 13.561 33.528 ;
     RECT  13.129 35.328 13.561 37.608 ;
     RECT  13.057 38.784 13.561 39.624 ;
     RECT  12.521 41.856 13.561 42.504 ;
     RECT  13.453 45.744 13.561 46.392 ;
     RECT  13.093 10.272 13.597 13.56 ;
     RECT  13.561 23.712 13.597 33.528 ;
     RECT  13.561 41.04 13.597 42.504 ;
     RECT  12.805 43.68 13.597 43.704 ;
     RECT  13.561 45.12 13.597 46.392 ;
     RECT  13.093 7.44 13.633 8.856 ;
     RECT  13.597 10.08 13.633 13.56 ;
     RECT  13.093 14.544 13.633 15.192 ;
     RECT  12.301 16.368 13.633 18.024 ;
     RECT  13.057 20.064 13.633 22.104 ;
     RECT  13.597 23.52 13.633 33.528 ;
     RECT  13.597 41.04 13.633 46.392 ;
     RECT  13.093 47.568 13.633 51.48 ;
     RECT  12.409 52.464 13.633 52.488 ;
     RECT  13.489 53.664 13.633 54.12 ;
     RECT  13.129 5.568 13.669 6.024 ;
     RECT  13.633 7.2 13.669 22.104 ;
     RECT  13.561 34.944 13.669 39.624 ;
     RECT  13.633 41.04 13.669 51.48 ;
     RECT  13.633 23.328 13.705 33.96 ;
     RECT  13.669 34.944 13.705 51.48 ;
     RECT  13.705 23.328 13.957 51.48 ;
     RECT  13.633 52.464 13.957 54.12 ;
     RECT  13.957 23.328 14.101 54.12 ;
     RECT  13.669 5.568 14.173 22.104 ;
     RECT  14.173 5.568 14.209 22.344 ;
     RECT  14.101 23.328 14.209 54.504 ;
     RECT  13.093 55.536 14.209 56.136 ;
     RECT  13.093 57.36 14.209 59.4 ;
     RECT  14.209 5.568 14.929 59.4 ;
     RECT  14.929 5.424 15.036 59.4 ;
     RECT  15.036 26.688 15.041 26.712 ;
    LAYER M5 ;
     RECT  0.192 1.285 0.216 1.381 ;
     RECT  0.096 1.381 0.216 1.427 ;
     RECT  2.4 2.137 2.52 2.151 ;
     RECT  5.1 2.137 5.22 2.151 ;
     RECT  7.8 2.137 7.92 2.151 ;
     RECT  10.5 2.137 10.62 2.151 ;
     RECT  2.4 2.151 2.712 5.605 ;
     RECT  5.1 2.151 5.412 5.653 ;
     RECT  10.5 2.151 10.812 5.893 ;
     RECT  2.4 5.605 3.432 6.037 ;
     RECT  4.992 5.653 5.412 6.037 ;
     RECT  2.4 6.037 5.412 6.323 ;
     RECT  7.8 2.151 8.112 6.805 ;
     RECT  3.888 6.323 5.412 7.285 ;
     RECT  3.888 7.285 6.216 7.765 ;
     RECT  2.4 6.323 2.712 7.957 ;
     RECT  3.84 7.765 6.216 7.957 ;
     RECT  7.8 6.805 8.568 7.957 ;
     RECT  7.44 7.957 8.568 9.011 ;
     RECT  2.4 7.957 6.216 9.587 ;
     RECT  7.8 9.011 8.568 10.261 ;
     RECT  9.744 5.893 10.812 10.261 ;
     RECT  2.4 9.587 5.976 10.789 ;
     RECT  2.4 10.789 6.168 11.459 ;
     RECT  3.696 11.459 6.168 12.229 ;
     RECT  7.8 10.261 10.812 12.229 ;
     RECT  2.4 11.459 2.712 12.469 ;
     RECT  3.696 12.229 10.812 12.469 ;
     RECT  2.4 12.469 10.812 12.611 ;
     RECT  2.4 12.611 8.664 13.091 ;
     RECT  2.4 13.091 2.712 14.725 ;
     RECT  3.696 13.091 8.664 14.725 ;
     RECT  2.4 14.725 8.664 14.819 ;
     RECT  5.1 14.819 8.664 15.781 ;
     RECT  9.744 12.611 10.812 15.781 ;
     RECT  2.4 14.819 4.008 15.971 ;
     RECT  5.1 15.781 10.812 16.309 ;
     RECT  4.992 16.309 10.812 16.451 ;
     RECT  2.4 15.971 3.912 17.413 ;
     RECT  5.1 16.451 10.812 17.413 ;
     RECT  2.4 17.413 10.812 19.861 ;
     RECT  0.096 1.427 0.12 29.269 ;
     RECT  0.096 29.269 0.264 29.459 ;
     RECT  2.4 19.861 10.92 44.483 ;
     RECT  2.4 44.483 3.864 48.515 ;
     RECT  5.1 44.483 10.92 48.515 ;
     RECT  7.104 48.515 10.92 50.483 ;
     RECT  7.104 50.483 9.336 51.395 ;
     RECT  7.104 51.395 8.808 51.731 ;
     RECT  10.5 50.483 10.92 52.499 ;
     RECT  7.44 51.731 8.808 54.179 ;
     RECT  7.44 54.179 8.28 55.571 ;
     RECT  2.4 48.515 3.384 55.907 ;
     RECT  5.1 48.515 5.544 57.443 ;
     RECT  7.8 55.571 8.28 57.971 ;
     RECT  2.4 55.907 2.712 62.649 ;
     RECT  5.1 57.443 5.412 62.649 ;
     RECT  7.8 57.971 8.112 62.649 ;
     RECT  10.5 52.499 10.812 62.649 ;
     RECT  2.4 62.649 2.52 62.663 ;
     RECT  5.1 62.649 5.22 62.663 ;
     RECT  7.8 62.649 7.92 62.663 ;
     RECT  10.5 62.649 10.62 62.663 ;
     RECT  2.712 6.323 3.888 7.765 ;
     RECT  8.568 6.805 9.744 10.261 ;
     RECT  2.712 7.765 3.84 7.957 ;
     RECT  6.216 7.957 7.44 9.011 ;
     RECT  5.976 9.587 6.168 10.789 ;
     RECT  2.712 11.459 3.696 12.469 ;
     RECT  8.664 12.611 9.744 15.781 ;
     RECT  2.712 13.091 3.696 14.725 ;
     RECT  4.008 14.819 5.1 15.971 ;
     RECT  3.912 15.971 5.1 16.309 ;
     RECT  3.912 16.309 4.992 16.451 ;
     RECT  3.912 16.451 5.1 17.413 ;
     RECT  3.864 44.483 5.1 48.515 ;
     RECT  9.336 50.483 10.5 51.395 ;
  END
END qwen_tx_rnep_r0
END LIBRARY
